VERSION 5.8 ;
BUSBITCHARS "[]" ;
DIVIDERCHAR "/" ;
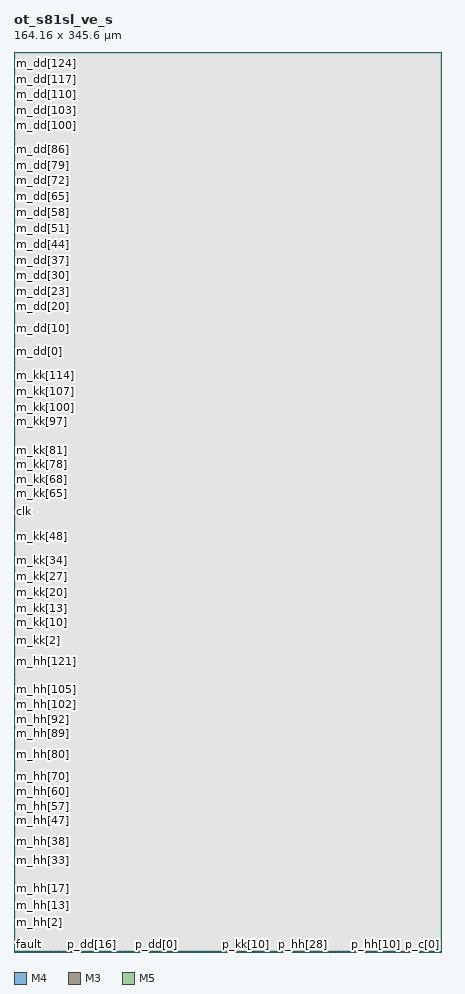
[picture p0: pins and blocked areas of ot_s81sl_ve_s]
MACRO ot_s81sl_ve_s
  CLASS BLOCK ;
  ORIGIN 0 0 ;
  FOREIGN ot_s81sl_ve_s 0 0 ;
  SIZE 164.160 BY 345.600 ;
  SYMMETRY X Y ;
  PIN clk
    DIRECTION INPUT ;
    USE SIGNAL ;
    PORT
      LAYER M4 ;
        RECT 0.0000 172.3200 0.0840 172.3440 ;
    END
  END clk
  PIN fault
    DIRECTION OUTPUT ;
    USE SIGNAL ;
    PORT
      LAYER M3 ;
        RECT 5.1120 0.0000 5.1300 0.0380 ;
    END
  END fault
  PIN m_dd[0]
    DIRECTION INPUT ;
    USE SIGNAL ;
    PORT
      LAYER M4 ;
        RECT 0.0000 230.4960 0.0840 230.5200 ;
    END
  END m_dd[0]
  PIN m_dd[100]
    DIRECTION INPUT ;
    USE SIGNAL ;
    PORT
      LAYER M4 ;
        RECT 0.0000 317.3760 0.0840 317.4000 ;
    END
  END m_dd[100]
  PIN m_dd[101]
    DIRECTION INPUT ;
    USE SIGNAL ;
    PORT
      LAYER M4 ;
        RECT 0.0000 318.2400 0.0840 318.2640 ;
    END
  END m_dd[101]
  PIN m_dd[102]
    DIRECTION INPUT ;
    USE SIGNAL ;
    PORT
      LAYER M4 ;
        RECT 0.0000 319.1040 0.0840 319.1280 ;
    END
  END m_dd[102]
  PIN m_dd[103]
    DIRECTION INPUT ;
    USE SIGNAL ;
    PORT
      LAYER M4 ;
        RECT 0.0000 319.9680 0.0840 319.9920 ;
    END
  END m_dd[103]
  PIN m_dd[104]
    DIRECTION INPUT ;
    USE SIGNAL ;
    PORT
      LAYER M4 ;
        RECT 0.0000 320.8320 0.0840 320.8560 ;
    END
  END m_dd[104]
  PIN m_dd[105]
    DIRECTION INPUT ;
    USE SIGNAL ;
    PORT
      LAYER M4 ;
        RECT 0.0000 321.6960 0.0840 321.7200 ;
    END
  END m_dd[105]
  PIN m_dd[106]
    DIRECTION INPUT ;
    USE SIGNAL ;
    PORT
      LAYER M4 ;
        RECT 0.0000 322.5600 0.0840 322.5840 ;
    END
  END m_dd[106]
  PIN m_dd[107]
    DIRECTION INPUT ;
    USE SIGNAL ;
    PORT
      LAYER M4 ;
        RECT 0.0000 323.4240 0.0840 323.4480 ;
    END
  END m_dd[107]
  PIN m_dd[108]
    DIRECTION INPUT ;
    USE SIGNAL ;
    PORT
      LAYER M4 ;
        RECT 0.0000 324.2880 0.0840 324.3120 ;
    END
  END m_dd[108]
  PIN m_dd[109]
    DIRECTION INPUT ;
    USE SIGNAL ;
    PORT
      LAYER M4 ;
        RECT 0.0000 325.2480 0.0840 325.2720 ;
    END
  END m_dd[109]
  PIN m_dd[10]
    DIRECTION INPUT ;
    USE SIGNAL ;
    PORT
      LAYER M4 ;
        RECT 0.0000 239.2320 0.0840 239.2560 ;
    END
  END m_dd[10]
  PIN m_dd[110]
    DIRECTION INPUT ;
    USE SIGNAL ;
    PORT
      LAYER M4 ;
        RECT 0.0000 326.1120 0.0840 326.1360 ;
    END
  END m_dd[110]
  PIN m_dd[111]
    DIRECTION INPUT ;
    USE SIGNAL ;
    PORT
      LAYER M4 ;
        RECT 0.0000 326.9760 0.0840 327.0000 ;
    END
  END m_dd[111]
  PIN m_dd[112]
    DIRECTION INPUT ;
    USE SIGNAL ;
    PORT
      LAYER M4 ;
        RECT 0.0000 327.8400 0.0840 327.8640 ;
    END
  END m_dd[112]
  PIN m_dd[113]
    DIRECTION INPUT ;
    USE SIGNAL ;
    PORT
      LAYER M4 ;
        RECT 0.0000 328.7040 0.0840 328.7280 ;
    END
  END m_dd[113]
  PIN m_dd[114]
    DIRECTION INPUT ;
    USE SIGNAL ;
    PORT
      LAYER M4 ;
        RECT 0.0000 329.5680 0.0840 329.5920 ;
    END
  END m_dd[114]
  PIN m_dd[115]
    DIRECTION INPUT ;
    USE SIGNAL ;
    PORT
      LAYER M4 ;
        RECT 0.0000 330.4320 0.0840 330.4560 ;
    END
  END m_dd[115]
  PIN m_dd[116]
    DIRECTION INPUT ;
    USE SIGNAL ;
    PORT
      LAYER M4 ;
        RECT 0.0000 331.2960 0.0840 331.3200 ;
    END
  END m_dd[116]
  PIN m_dd[117]
    DIRECTION INPUT ;
    USE SIGNAL ;
    PORT
      LAYER M4 ;
        RECT 0.0000 332.1600 0.0840 332.1840 ;
    END
  END m_dd[117]
  PIN m_dd[118]
    DIRECTION INPUT ;
    USE SIGNAL ;
    PORT
      LAYER M4 ;
        RECT 0.0000 333.0240 0.0840 333.0480 ;
    END
  END m_dd[118]
  PIN m_dd[119]
    DIRECTION INPUT ;
    USE SIGNAL ;
    PORT
      LAYER M4 ;
        RECT 0.0000 333.8880 0.0840 333.9120 ;
    END
  END m_dd[119]
  PIN m_dd[11]
    DIRECTION INPUT ;
    USE SIGNAL ;
    PORT
      LAYER M4 ;
        RECT 0.0000 240.0960 0.0840 240.1200 ;
    END
  END m_dd[11]
  PIN m_dd[120]
    DIRECTION INPUT ;
    USE SIGNAL ;
    PORT
      LAYER M4 ;
        RECT 0.0000 334.7520 0.0840 334.7760 ;
    END
  END m_dd[120]
  PIN m_dd[121]
    DIRECTION INPUT ;
    USE SIGNAL ;
    PORT
      LAYER M4 ;
        RECT 0.0000 335.6160 0.0840 335.6400 ;
    END
  END m_dd[121]
  PIN m_dd[122]
    DIRECTION INPUT ;
    USE SIGNAL ;
    PORT
      LAYER M4 ;
        RECT 0.0000 336.4800 0.0840 336.5040 ;
    END
  END m_dd[122]
  PIN m_dd[123]
    DIRECTION INPUT ;
    USE SIGNAL ;
    PORT
      LAYER M4 ;
        RECT 0.0000 337.3440 0.0840 337.3680 ;
    END
  END m_dd[123]
  PIN m_dd[124]
    DIRECTION INPUT ;
    USE SIGNAL ;
    PORT
      LAYER M4 ;
        RECT 0.0000 338.2080 0.0840 338.2320 ;
    END
  END m_dd[124]
  PIN m_dd[125]
    DIRECTION INPUT ;
    USE SIGNAL ;
    PORT
      LAYER M4 ;
        RECT 0.0000 339.0720 0.0840 339.0960 ;
    END
  END m_dd[125]
  PIN m_dd[126]
    DIRECTION INPUT ;
    USE SIGNAL ;
    PORT
      LAYER M4 ;
        RECT 0.0000 339.9360 0.0840 339.9600 ;
    END
  END m_dd[126]
  PIN m_dd[127]
    DIRECTION INPUT ;
    USE SIGNAL ;
    PORT
      LAYER M4 ;
        RECT 0.0000 340.8000 0.0840 340.8240 ;
    END
  END m_dd[127]
  PIN m_dd[12]
    DIRECTION INPUT ;
    USE SIGNAL ;
    PORT
      LAYER M4 ;
        RECT 0.0000 240.9600 0.0840 240.9840 ;
    END
  END m_dd[12]
  PIN m_dd[13]
    DIRECTION INPUT ;
    USE SIGNAL ;
    PORT
      LAYER M4 ;
        RECT 0.0000 241.8240 0.0840 241.8480 ;
    END
  END m_dd[13]
  PIN m_dd[14]
    DIRECTION INPUT ;
    USE SIGNAL ;
    PORT
      LAYER M4 ;
        RECT 0.0000 242.6880 0.0840 242.7120 ;
    END
  END m_dd[14]
  PIN m_dd[15]
    DIRECTION INPUT ;
    USE SIGNAL ;
    PORT
      LAYER M4 ;
        RECT 0.0000 243.5520 0.0840 243.5760 ;
    END
  END m_dd[15]
  PIN m_dd[16]
    DIRECTION INPUT ;
    USE SIGNAL ;
    PORT
      LAYER M4 ;
        RECT 0.0000 244.4160 0.0840 244.4400 ;
    END
  END m_dd[16]
  PIN m_dd[17]
    DIRECTION INPUT ;
    USE SIGNAL ;
    PORT
      LAYER M4 ;
        RECT 0.0000 245.2800 0.0840 245.3040 ;
    END
  END m_dd[17]
  PIN m_dd[18]
    DIRECTION INPUT ;
    USE SIGNAL ;
    PORT
      LAYER M4 ;
        RECT 0.0000 246.1440 0.0840 246.1680 ;
    END
  END m_dd[18]
  PIN m_dd[19]
    DIRECTION INPUT ;
    USE SIGNAL ;
    PORT
      LAYER M4 ;
        RECT 0.0000 247.0080 0.0840 247.0320 ;
    END
  END m_dd[19]
  PIN m_dd[1]
    DIRECTION INPUT ;
    USE SIGNAL ;
    PORT
      LAYER M4 ;
        RECT 0.0000 231.4560 0.0840 231.4800 ;
    END
  END m_dd[1]
  PIN m_dd[20]
    DIRECTION INPUT ;
    USE SIGNAL ;
    PORT
      LAYER M4 ;
        RECT 0.0000 247.8720 0.0840 247.8960 ;
    END
  END m_dd[20]
  PIN m_dd[21]
    DIRECTION INPUT ;
    USE SIGNAL ;
    PORT
      LAYER M4 ;
        RECT 0.0000 248.7360 0.0840 248.7600 ;
    END
  END m_dd[21]
  PIN m_dd[22]
    DIRECTION INPUT ;
    USE SIGNAL ;
    PORT
      LAYER M4 ;
        RECT 0.0000 249.6000 0.0840 249.6240 ;
    END
  END m_dd[22]
  PIN m_dd[23]
    DIRECTION INPUT ;
    USE SIGNAL ;
    PORT
      LAYER M4 ;
        RECT 0.0000 250.5600 0.0840 250.5840 ;
    END
  END m_dd[23]
  PIN m_dd[24]
    DIRECTION INPUT ;
    USE SIGNAL ;
    PORT
      LAYER M4 ;
        RECT 0.0000 251.4240 0.0840 251.4480 ;
    END
  END m_dd[24]
  PIN m_dd[25]
    DIRECTION INPUT ;
    USE SIGNAL ;
    PORT
      LAYER M4 ;
        RECT 0.0000 252.2880 0.0840 252.3120 ;
    END
  END m_dd[25]
  PIN m_dd[26]
    DIRECTION INPUT ;
    USE SIGNAL ;
    PORT
      LAYER M4 ;
        RECT 0.0000 253.1520 0.0840 253.1760 ;
    END
  END m_dd[26]
  PIN m_dd[27]
    DIRECTION INPUT ;
    USE SIGNAL ;
    PORT
      LAYER M4 ;
        RECT 0.0000 254.0160 0.0840 254.0400 ;
    END
  END m_dd[27]
  PIN m_dd[28]
    DIRECTION INPUT ;
    USE SIGNAL ;
    PORT
      LAYER M4 ;
        RECT 0.0000 254.8800 0.0840 254.9040 ;
    END
  END m_dd[28]
  PIN m_dd[29]
    DIRECTION INPUT ;
    USE SIGNAL ;
    PORT
      LAYER M4 ;
        RECT 0.0000 255.7440 0.0840 255.7680 ;
    END
  END m_dd[29]
  PIN m_dd[2]
    DIRECTION INPUT ;
    USE SIGNAL ;
    PORT
      LAYER M4 ;
        RECT 0.0000 232.3200 0.0840 232.3440 ;
    END
  END m_dd[2]
  PIN m_dd[30]
    DIRECTION INPUT ;
    USE SIGNAL ;
    PORT
      LAYER M4 ;
        RECT 0.0000 256.6080 0.0840 256.6320 ;
    END
  END m_dd[30]
  PIN m_dd[31]
    DIRECTION INPUT ;
    USE SIGNAL ;
    PORT
      LAYER M4 ;
        RECT 0.0000 257.4720 0.0840 257.4960 ;
    END
  END m_dd[31]
  PIN m_dd[32]
    DIRECTION INPUT ;
    USE SIGNAL ;
    PORT
      LAYER M4 ;
        RECT 0.0000 258.3360 0.0840 258.3600 ;
    END
  END m_dd[32]
  PIN m_dd[33]
    DIRECTION INPUT ;
    USE SIGNAL ;
    PORT
      LAYER M4 ;
        RECT 0.0000 259.2000 0.0840 259.2240 ;
    END
  END m_dd[33]
  PIN m_dd[34]
    DIRECTION INPUT ;
    USE SIGNAL ;
    PORT
      LAYER M4 ;
        RECT 0.0000 260.0640 0.0840 260.0880 ;
    END
  END m_dd[34]
  PIN m_dd[35]
    DIRECTION INPUT ;
    USE SIGNAL ;
    PORT
      LAYER M4 ;
        RECT 0.0000 260.9280 0.0840 260.9520 ;
    END
  END m_dd[35]
  PIN m_dd[36]
    DIRECTION INPUT ;
    USE SIGNAL ;
    PORT
      LAYER M4 ;
        RECT 0.0000 261.7920 0.0840 261.8160 ;
    END
  END m_dd[36]
  PIN m_dd[37]
    DIRECTION INPUT ;
    USE SIGNAL ;
    PORT
      LAYER M4 ;
        RECT 0.0000 262.6560 0.0840 262.6800 ;
    END
  END m_dd[37]
  PIN m_dd[38]
    DIRECTION INPUT ;
    USE SIGNAL ;
    PORT
      LAYER M4 ;
        RECT 0.0000 263.5200 0.0840 263.5440 ;
    END
  END m_dd[38]
  PIN m_dd[39]
    DIRECTION INPUT ;
    USE SIGNAL ;
    PORT
      LAYER M4 ;
        RECT 0.0000 264.3840 0.0840 264.4080 ;
    END
  END m_dd[39]
  PIN m_dd[3]
    DIRECTION INPUT ;
    USE SIGNAL ;
    PORT
      LAYER M4 ;
        RECT 0.0000 233.1840 0.0840 233.2080 ;
    END
  END m_dd[3]
  PIN m_dd[40]
    DIRECTION INPUT ;
    USE SIGNAL ;
    PORT
      LAYER M4 ;
        RECT 0.0000 265.2480 0.0840 265.2720 ;
    END
  END m_dd[40]
  PIN m_dd[41]
    DIRECTION INPUT ;
    USE SIGNAL ;
    PORT
      LAYER M4 ;
        RECT 0.0000 266.1120 0.0840 266.1360 ;
    END
  END m_dd[41]
  PIN m_dd[42]
    DIRECTION INPUT ;
    USE SIGNAL ;
    PORT
      LAYER M4 ;
        RECT 0.0000 266.9760 0.0840 267.0000 ;
    END
  END m_dd[42]
  PIN m_dd[43]
    DIRECTION INPUT ;
    USE SIGNAL ;
    PORT
      LAYER M4 ;
        RECT 0.0000 267.8400 0.0840 267.8640 ;
    END
  END m_dd[43]
  PIN m_dd[44]
    DIRECTION INPUT ;
    USE SIGNAL ;
    PORT
      LAYER M4 ;
        RECT 0.0000 268.8000 0.0840 268.8240 ;
    END
  END m_dd[44]
  PIN m_dd[45]
    DIRECTION INPUT ;
    USE SIGNAL ;
    PORT
      LAYER M4 ;
        RECT 0.0000 269.6640 0.0840 269.6880 ;
    END
  END m_dd[45]
  PIN m_dd[46]
    DIRECTION INPUT ;
    USE SIGNAL ;
    PORT
      LAYER M4 ;
        RECT 0.0000 270.5280 0.0840 270.5520 ;
    END
  END m_dd[46]
  PIN m_dd[47]
    DIRECTION INPUT ;
    USE SIGNAL ;
    PORT
      LAYER M4 ;
        RECT 0.0000 271.3920 0.0840 271.4160 ;
    END
  END m_dd[47]
  PIN m_dd[48]
    DIRECTION INPUT ;
    USE SIGNAL ;
    PORT
      LAYER M4 ;
        RECT 0.0000 272.2560 0.0840 272.2800 ;
    END
  END m_dd[48]
  PIN m_dd[49]
    DIRECTION INPUT ;
    USE SIGNAL ;
    PORT
      LAYER M4 ;
        RECT 0.0000 273.1200 0.0840 273.1440 ;
    END
  END m_dd[49]
  PIN m_dd[4]
    DIRECTION INPUT ;
    USE SIGNAL ;
    PORT
      LAYER M4 ;
        RECT 0.0000 234.0480 0.0840 234.0720 ;
    END
  END m_dd[4]
  PIN m_dd[50]
    DIRECTION INPUT ;
    USE SIGNAL ;
    PORT
      LAYER M4 ;
        RECT 0.0000 273.9840 0.0840 274.0080 ;
    END
  END m_dd[50]
  PIN m_dd[51]
    DIRECTION INPUT ;
    USE SIGNAL ;
    PORT
      LAYER M4 ;
        RECT 0.0000 274.8480 0.0840 274.8720 ;
    END
  END m_dd[51]
  PIN m_dd[52]
    DIRECTION INPUT ;
    USE SIGNAL ;
    PORT
      LAYER M4 ;
        RECT 0.0000 275.7120 0.0840 275.7360 ;
    END
  END m_dd[52]
  PIN m_dd[53]
    DIRECTION INPUT ;
    USE SIGNAL ;
    PORT
      LAYER M4 ;
        RECT 0.0000 276.5760 0.0840 276.6000 ;
    END
  END m_dd[53]
  PIN m_dd[54]
    DIRECTION INPUT ;
    USE SIGNAL ;
    PORT
      LAYER M4 ;
        RECT 0.0000 277.4400 0.0840 277.4640 ;
    END
  END m_dd[54]
  PIN m_dd[55]
    DIRECTION INPUT ;
    USE SIGNAL ;
    PORT
      LAYER M4 ;
        RECT 0.0000 278.3040 0.0840 278.3280 ;
    END
  END m_dd[55]
  PIN m_dd[56]
    DIRECTION INPUT ;
    USE SIGNAL ;
    PORT
      LAYER M4 ;
        RECT 0.0000 279.1680 0.0840 279.1920 ;
    END
  END m_dd[56]
  PIN m_dd[57]
    DIRECTION INPUT ;
    USE SIGNAL ;
    PORT
      LAYER M4 ;
        RECT 0.0000 280.0320 0.0840 280.0560 ;
    END
  END m_dd[57]
  PIN m_dd[58]
    DIRECTION INPUT ;
    USE SIGNAL ;
    PORT
      LAYER M4 ;
        RECT 0.0000 280.8960 0.0840 280.9200 ;
    END
  END m_dd[58]
  PIN m_dd[59]
    DIRECTION INPUT ;
    USE SIGNAL ;
    PORT
      LAYER M4 ;
        RECT 0.0000 281.7600 0.0840 281.7840 ;
    END
  END m_dd[59]
  PIN m_dd[5]
    DIRECTION INPUT ;
    USE SIGNAL ;
    PORT
      LAYER M4 ;
        RECT 0.0000 234.9120 0.0840 234.9360 ;
    END
  END m_dd[5]
  PIN m_dd[60]
    DIRECTION INPUT ;
    USE SIGNAL ;
    PORT
      LAYER M4 ;
        RECT 0.0000 282.6240 0.0840 282.6480 ;
    END
  END m_dd[60]
  PIN m_dd[61]
    DIRECTION INPUT ;
    USE SIGNAL ;
    PORT
      LAYER M4 ;
        RECT 0.0000 283.4880 0.0840 283.5120 ;
    END
  END m_dd[61]
  PIN m_dd[62]
    DIRECTION INPUT ;
    USE SIGNAL ;
    PORT
      LAYER M4 ;
        RECT 0.0000 284.3520 0.0840 284.3760 ;
    END
  END m_dd[62]
  PIN m_dd[63]
    DIRECTION INPUT ;
    USE SIGNAL ;
    PORT
      LAYER M4 ;
        RECT 0.0000 285.2160 0.0840 285.2400 ;
    END
  END m_dd[63]
  PIN m_dd[64]
    DIRECTION INPUT ;
    USE SIGNAL ;
    PORT
      LAYER M4 ;
        RECT 0.0000 286.0800 0.0840 286.1040 ;
    END
  END m_dd[64]
  PIN m_dd[65]
    DIRECTION INPUT ;
    USE SIGNAL ;
    PORT
      LAYER M4 ;
        RECT 0.0000 286.9440 0.0840 286.9680 ;
    END
  END m_dd[65]
  PIN m_dd[66]
    DIRECTION INPUT ;
    USE SIGNAL ;
    PORT
      LAYER M4 ;
        RECT 0.0000 287.9040 0.0840 287.9280 ;
    END
  END m_dd[66]
  PIN m_dd[67]
    DIRECTION INPUT ;
    USE SIGNAL ;
    PORT
      LAYER M4 ;
        RECT 0.0000 288.7680 0.0840 288.7920 ;
    END
  END m_dd[67]
  PIN m_dd[68]
    DIRECTION INPUT ;
    USE SIGNAL ;
    PORT
      LAYER M4 ;
        RECT 0.0000 289.6320 0.0840 289.6560 ;
    END
  END m_dd[68]
  PIN m_dd[69]
    DIRECTION INPUT ;
    USE SIGNAL ;
    PORT
      LAYER M4 ;
        RECT 0.0000 290.4960 0.0840 290.5200 ;
    END
  END m_dd[69]
  PIN m_dd[6]
    DIRECTION INPUT ;
    USE SIGNAL ;
    PORT
      LAYER M4 ;
        RECT 0.0000 235.7760 0.0840 235.8000 ;
    END
  END m_dd[6]
  PIN m_dd[70]
    DIRECTION INPUT ;
    USE SIGNAL ;
    PORT
      LAYER M4 ;
        RECT 0.0000 291.3600 0.0840 291.3840 ;
    END
  END m_dd[70]
  PIN m_dd[71]
    DIRECTION INPUT ;
    USE SIGNAL ;
    PORT
      LAYER M4 ;
        RECT 0.0000 292.2240 0.0840 292.2480 ;
    END
  END m_dd[71]
  PIN m_dd[72]
    DIRECTION INPUT ;
    USE SIGNAL ;
    PORT
      LAYER M4 ;
        RECT 0.0000 293.0880 0.0840 293.1120 ;
    END
  END m_dd[72]
  PIN m_dd[73]
    DIRECTION INPUT ;
    USE SIGNAL ;
    PORT
      LAYER M4 ;
        RECT 0.0000 293.9520 0.0840 293.9760 ;
    END
  END m_dd[73]
  PIN m_dd[74]
    DIRECTION INPUT ;
    USE SIGNAL ;
    PORT
      LAYER M4 ;
        RECT 0.0000 294.8160 0.0840 294.8400 ;
    END
  END m_dd[74]
  PIN m_dd[75]
    DIRECTION INPUT ;
    USE SIGNAL ;
    PORT
      LAYER M4 ;
        RECT 0.0000 295.6800 0.0840 295.7040 ;
    END
  END m_dd[75]
  PIN m_dd[76]
    DIRECTION INPUT ;
    USE SIGNAL ;
    PORT
      LAYER M4 ;
        RECT 0.0000 296.5440 0.0840 296.5680 ;
    END
  END m_dd[76]
  PIN m_dd[77]
    DIRECTION INPUT ;
    USE SIGNAL ;
    PORT
      LAYER M4 ;
        RECT 0.0000 297.4080 0.0840 297.4320 ;
    END
  END m_dd[77]
  PIN m_dd[78]
    DIRECTION INPUT ;
    USE SIGNAL ;
    PORT
      LAYER M4 ;
        RECT 0.0000 298.2720 0.0840 298.2960 ;
    END
  END m_dd[78]
  PIN m_dd[79]
    DIRECTION INPUT ;
    USE SIGNAL ;
    PORT
      LAYER M4 ;
        RECT 0.0000 299.1360 0.0840 299.1600 ;
    END
  END m_dd[79]
  PIN m_dd[7]
    DIRECTION INPUT ;
    USE SIGNAL ;
    PORT
      LAYER M4 ;
        RECT 0.0000 236.6400 0.0840 236.6640 ;
    END
  END m_dd[7]
  PIN m_dd[80]
    DIRECTION INPUT ;
    USE SIGNAL ;
    PORT
      LAYER M4 ;
        RECT 0.0000 300.0000 0.0840 300.0240 ;
    END
  END m_dd[80]
  PIN m_dd[81]
    DIRECTION INPUT ;
    USE SIGNAL ;
    PORT
      LAYER M4 ;
        RECT 0.0000 300.8640 0.0840 300.8880 ;
    END
  END m_dd[81]
  PIN m_dd[82]
    DIRECTION INPUT ;
    USE SIGNAL ;
    PORT
      LAYER M4 ;
        RECT 0.0000 301.7280 0.0840 301.7520 ;
    END
  END m_dd[82]
  PIN m_dd[83]
    DIRECTION INPUT ;
    USE SIGNAL ;
    PORT
      LAYER M4 ;
        RECT 0.0000 302.5920 0.0840 302.6160 ;
    END
  END m_dd[83]
  PIN m_dd[84]
    DIRECTION INPUT ;
    USE SIGNAL ;
    PORT
      LAYER M4 ;
        RECT 0.0000 303.4560 0.0840 303.4800 ;
    END
  END m_dd[84]
  PIN m_dd[85]
    DIRECTION INPUT ;
    USE SIGNAL ;
    PORT
      LAYER M4 ;
        RECT 0.0000 304.3200 0.0840 304.3440 ;
    END
  END m_dd[85]
  PIN m_dd[86]
    DIRECTION INPUT ;
    USE SIGNAL ;
    PORT
      LAYER M4 ;
        RECT 0.0000 305.1840 0.0840 305.2080 ;
    END
  END m_dd[86]
  PIN m_dd[87]
    DIRECTION INPUT ;
    USE SIGNAL ;
    PORT
      LAYER M4 ;
        RECT 0.0000 306.0480 0.0840 306.0720 ;
    END
  END m_dd[87]
  PIN m_dd[88]
    DIRECTION INPUT ;
    USE SIGNAL ;
    PORT
      LAYER M4 ;
        RECT 0.0000 307.0080 0.0840 307.0320 ;
    END
  END m_dd[88]
  PIN m_dd[89]
    DIRECTION INPUT ;
    USE SIGNAL ;
    PORT
      LAYER M4 ;
        RECT 0.0000 307.8720 0.0840 307.8960 ;
    END
  END m_dd[89]
  PIN m_dd[8]
    DIRECTION INPUT ;
    USE SIGNAL ;
    PORT
      LAYER M4 ;
        RECT 0.0000 237.5040 0.0840 237.5280 ;
    END
  END m_dd[8]
  PIN m_dd[90]
    DIRECTION INPUT ;
    USE SIGNAL ;
    PORT
      LAYER M4 ;
        RECT 0.0000 308.7360 0.0840 308.7600 ;
    END
  END m_dd[90]
  PIN m_dd[91]
    DIRECTION INPUT ;
    USE SIGNAL ;
    PORT
      LAYER M4 ;
        RECT 0.0000 309.6000 0.0840 309.6240 ;
    END
  END m_dd[91]
  PIN m_dd[92]
    DIRECTION INPUT ;
    USE SIGNAL ;
    PORT
      LAYER M4 ;
        RECT 0.0000 310.4640 0.0840 310.4880 ;
    END
  END m_dd[92]
  PIN m_dd[93]
    DIRECTION INPUT ;
    USE SIGNAL ;
    PORT
      LAYER M4 ;
        RECT 0.0000 311.3280 0.0840 311.3520 ;
    END
  END m_dd[93]
  PIN m_dd[94]
    DIRECTION INPUT ;
    USE SIGNAL ;
    PORT
      LAYER M4 ;
        RECT 0.0000 312.1920 0.0840 312.2160 ;
    END
  END m_dd[94]
  PIN m_dd[95]
    DIRECTION INPUT ;
    USE SIGNAL ;
    PORT
      LAYER M4 ;
        RECT 0.0000 313.0560 0.0840 313.0800 ;
    END
  END m_dd[95]
  PIN m_dd[96]
    DIRECTION INPUT ;
    USE SIGNAL ;
    PORT
      LAYER M4 ;
        RECT 0.0000 313.9200 0.0840 313.9440 ;
    END
  END m_dd[96]
  PIN m_dd[97]
    DIRECTION INPUT ;
    USE SIGNAL ;
    PORT
      LAYER M4 ;
        RECT 0.0000 314.7840 0.0840 314.8080 ;
    END
  END m_dd[97]
  PIN m_dd[98]
    DIRECTION INPUT ;
    USE SIGNAL ;
    PORT
      LAYER M4 ;
        RECT 0.0000 315.6480 0.0840 315.6720 ;
    END
  END m_dd[98]
  PIN m_dd[99]
    DIRECTION INPUT ;
    USE SIGNAL ;
    PORT
      LAYER M4 ;
        RECT 0.0000 316.5120 0.0840 316.5360 ;
    END
  END m_dd[99]
  PIN m_dd[9]
    DIRECTION INPUT ;
    USE SIGNAL ;
    PORT
      LAYER M4 ;
        RECT 0.0000 238.3680 0.0840 238.3920 ;
    END
  END m_dd[9]
  PIN m_hh[0]
    DIRECTION INPUT ;
    USE SIGNAL ;
    PORT
      LAYER M4 ;
        RECT 0.0000 6.4320 0.0840 6.4560 ;
    END
  END m_hh[0]
  PIN m_hh[100]
    DIRECTION INPUT ;
    USE SIGNAL ;
    PORT
      LAYER M4 ;
        RECT 0.0000 93.3120 0.0840 93.3360 ;
    END
  END m_hh[100]
  PIN m_hh[101]
    DIRECTION INPUT ;
    USE SIGNAL ;
    PORT
      LAYER M4 ;
        RECT 0.0000 94.1760 0.0840 94.2000 ;
    END
  END m_hh[101]
  PIN m_hh[102]
    DIRECTION INPUT ;
    USE SIGNAL ;
    PORT
      LAYER M4 ;
        RECT 0.0000 95.0400 0.0840 95.0640 ;
    END
  END m_hh[102]
  PIN m_hh[103]
    DIRECTION INPUT ;
    USE SIGNAL ;
    PORT
      LAYER M4 ;
        RECT 0.0000 95.9040 0.0840 95.9280 ;
    END
  END m_hh[103]
  PIN m_hh[104]
    DIRECTION INPUT ;
    USE SIGNAL ;
    PORT
      LAYER M4 ;
        RECT 0.0000 96.7680 0.0840 96.7920 ;
    END
  END m_hh[104]
  PIN m_hh[105]
    DIRECTION INPUT ;
    USE SIGNAL ;
    PORT
      LAYER M4 ;
        RECT 0.0000 97.6320 0.0840 97.6560 ;
    END
  END m_hh[105]
  PIN m_hh[106]
    DIRECTION INPUT ;
    USE SIGNAL ;
    PORT
      LAYER M4 ;
        RECT 0.0000 98.4960 0.0840 98.5200 ;
    END
  END m_hh[106]
  PIN m_hh[107]
    DIRECTION INPUT ;
    USE SIGNAL ;
    PORT
      LAYER M4 ;
        RECT 0.0000 99.3600 0.0840 99.3840 ;
    END
  END m_hh[107]
  PIN m_hh[108]
    DIRECTION INPUT ;
    USE SIGNAL ;
    PORT
      LAYER M4 ;
        RECT 0.0000 100.3200 0.0840 100.3440 ;
    END
  END m_hh[108]
  PIN m_hh[109]
    DIRECTION INPUT ;
    USE SIGNAL ;
    PORT
      LAYER M4 ;
        RECT 0.0000 101.1840 0.0840 101.2080 ;
    END
  END m_hh[109]
  PIN m_hh[10]
    DIRECTION INPUT ;
    USE SIGNAL ;
    PORT
      LAYER M4 ;
        RECT 0.0000 15.1680 0.0840 15.1920 ;
    END
  END m_hh[10]
  PIN m_hh[110]
    DIRECTION INPUT ;
    USE SIGNAL ;
    PORT
      LAYER M4 ;
        RECT 0.0000 102.0480 0.0840 102.0720 ;
    END
  END m_hh[110]
  PIN m_hh[111]
    DIRECTION INPUT ;
    USE SIGNAL ;
    PORT
      LAYER M4 ;
        RECT 0.0000 102.9120 0.0840 102.9360 ;
    END
  END m_hh[111]
  PIN m_hh[112]
    DIRECTION INPUT ;
    USE SIGNAL ;
    PORT
      LAYER M4 ;
        RECT 0.0000 103.7760 0.0840 103.8000 ;
    END
  END m_hh[112]
  PIN m_hh[113]
    DIRECTION INPUT ;
    USE SIGNAL ;
    PORT
      LAYER M4 ;
        RECT 0.0000 104.6400 0.0840 104.6640 ;
    END
  END m_hh[113]
  PIN m_hh[114]
    DIRECTION INPUT ;
    USE SIGNAL ;
    PORT
      LAYER M4 ;
        RECT 0.0000 105.5040 0.0840 105.5280 ;
    END
  END m_hh[114]
  PIN m_hh[115]
    DIRECTION INPUT ;
    USE SIGNAL ;
    PORT
      LAYER M4 ;
        RECT 0.0000 106.3680 0.0840 106.3920 ;
    END
  END m_hh[115]
  PIN m_hh[116]
    DIRECTION INPUT ;
    USE SIGNAL ;
    PORT
      LAYER M4 ;
        RECT 0.0000 107.2320 0.0840 107.2560 ;
    END
  END m_hh[116]
  PIN m_hh[117]
    DIRECTION INPUT ;
    USE SIGNAL ;
    PORT
      LAYER M4 ;
        RECT 0.0000 108.0960 0.0840 108.1200 ;
    END
  END m_hh[117]
  PIN m_hh[118]
    DIRECTION INPUT ;
    USE SIGNAL ;
    PORT
      LAYER M4 ;
        RECT 0.0000 108.9600 0.0840 108.9840 ;
    END
  END m_hh[118]
  PIN m_hh[119]
    DIRECTION INPUT ;
    USE SIGNAL ;
    PORT
      LAYER M4 ;
        RECT 0.0000 109.8240 0.0840 109.8480 ;
    END
  END m_hh[119]
  PIN m_hh[11]
    DIRECTION INPUT ;
    USE SIGNAL ;
    PORT
      LAYER M4 ;
        RECT 0.0000 16.0320 0.0840 16.0560 ;
    END
  END m_hh[11]
  PIN m_hh[120]
    DIRECTION INPUT ;
    USE SIGNAL ;
    PORT
      LAYER M4 ;
        RECT 0.0000 110.6880 0.0840 110.7120 ;
    END
  END m_hh[120]
  PIN m_hh[121]
    DIRECTION INPUT ;
    USE SIGNAL ;
    PORT
      LAYER M4 ;
        RECT 0.0000 111.5520 0.0840 111.5760 ;
    END
  END m_hh[121]
  PIN m_hh[122]
    DIRECTION INPUT ;
    USE SIGNAL ;
    PORT
      LAYER M4 ;
        RECT 0.0000 112.4160 0.0840 112.4400 ;
    END
  END m_hh[122]
  PIN m_hh[123]
    DIRECTION INPUT ;
    USE SIGNAL ;
    PORT
      LAYER M4 ;
        RECT 0.0000 113.2800 0.0840 113.3040 ;
    END
  END m_hh[123]
  PIN m_hh[124]
    DIRECTION INPUT ;
    USE SIGNAL ;
    PORT
      LAYER M4 ;
        RECT 0.0000 114.1440 0.0840 114.1680 ;
    END
  END m_hh[124]
  PIN m_hh[125]
    DIRECTION INPUT ;
    USE SIGNAL ;
    PORT
      LAYER M4 ;
        RECT 0.0000 115.0080 0.0840 115.0320 ;
    END
  END m_hh[125]
  PIN m_hh[126]
    DIRECTION INPUT ;
    USE SIGNAL ;
    PORT
      LAYER M4 ;
        RECT 0.0000 115.8720 0.0840 115.8960 ;
    END
  END m_hh[126]
  PIN m_hh[127]
    DIRECTION INPUT ;
    USE SIGNAL ;
    PORT
      LAYER M4 ;
        RECT 0.0000 116.7360 0.0840 116.7600 ;
    END
  END m_hh[127]
  PIN m_hh[12]
    DIRECTION INPUT ;
    USE SIGNAL ;
    PORT
      LAYER M4 ;
        RECT 0.0000 16.8960 0.0840 16.9200 ;
    END
  END m_hh[12]
  PIN m_hh[13]
    DIRECTION INPUT ;
    USE SIGNAL ;
    PORT
      LAYER M4 ;
        RECT 0.0000 17.7600 0.0840 17.7840 ;
    END
  END m_hh[13]
  PIN m_hh[14]
    DIRECTION INPUT ;
    USE SIGNAL ;
    PORT
      LAYER M4 ;
        RECT 0.0000 18.6240 0.0840 18.6480 ;
    END
  END m_hh[14]
  PIN m_hh[15]
    DIRECTION INPUT ;
    USE SIGNAL ;
    PORT
      LAYER M4 ;
        RECT 0.0000 19.4880 0.0840 19.5120 ;
    END
  END m_hh[15]
  PIN m_hh[16]
    DIRECTION INPUT ;
    USE SIGNAL ;
    PORT
      LAYER M4 ;
        RECT 0.0000 20.3520 0.0840 20.3760 ;
    END
  END m_hh[16]
  PIN m_hh[17]
    DIRECTION INPUT ;
    USE SIGNAL ;
    PORT
      LAYER M4 ;
        RECT 0.0000 21.2160 0.0840 21.2400 ;
    END
  END m_hh[17]
  PIN m_hh[18]
    DIRECTION INPUT ;
    USE SIGNAL ;
    PORT
      LAYER M4 ;
        RECT 0.0000 22.0800 0.0840 22.1040 ;
    END
  END m_hh[18]
  PIN m_hh[19]
    DIRECTION INPUT ;
    USE SIGNAL ;
    PORT
      LAYER M4 ;
        RECT 0.0000 22.9440 0.0840 22.9680 ;
    END
  END m_hh[19]
  PIN m_hh[1]
    DIRECTION INPUT ;
    USE SIGNAL ;
    PORT
      LAYER M4 ;
        RECT 0.0000 7.3920 0.0840 7.4160 ;
    END
  END m_hh[1]
  PIN m_hh[20]
    DIRECTION INPUT ;
    USE SIGNAL ;
    PORT
      LAYER M4 ;
        RECT 0.0000 23.8080 0.0840 23.8320 ;
    END
  END m_hh[20]
  PIN m_hh[21]
    DIRECTION INPUT ;
    USE SIGNAL ;
    PORT
      LAYER M4 ;
        RECT 0.0000 24.6720 0.0840 24.6960 ;
    END
  END m_hh[21]
  PIN m_hh[22]
    DIRECTION INPUT ;
    USE SIGNAL ;
    PORT
      LAYER M4 ;
        RECT 0.0000 25.6320 0.0840 25.6560 ;
    END
  END m_hh[22]
  PIN m_hh[23]
    DIRECTION INPUT ;
    USE SIGNAL ;
    PORT
      LAYER M4 ;
        RECT 0.0000 26.4960 0.0840 26.5200 ;
    END
  END m_hh[23]
  PIN m_hh[24]
    DIRECTION INPUT ;
    USE SIGNAL ;
    PORT
      LAYER M4 ;
        RECT 0.0000 27.3600 0.0840 27.3840 ;
    END
  END m_hh[24]
  PIN m_hh[25]
    DIRECTION INPUT ;
    USE SIGNAL ;
    PORT
      LAYER M4 ;
        RECT 0.0000 28.2240 0.0840 28.2480 ;
    END
  END m_hh[25]
  PIN m_hh[26]
    DIRECTION INPUT ;
    USE SIGNAL ;
    PORT
      LAYER M4 ;
        RECT 0.0000 29.0880 0.0840 29.1120 ;
    END
  END m_hh[26]
  PIN m_hh[27]
    DIRECTION INPUT ;
    USE SIGNAL ;
    PORT
      LAYER M4 ;
        RECT 0.0000 29.9520 0.0840 29.9760 ;
    END
  END m_hh[27]
  PIN m_hh[28]
    DIRECTION INPUT ;
    USE SIGNAL ;
    PORT
      LAYER M4 ;
        RECT 0.0000 30.8160 0.0840 30.8400 ;
    END
  END m_hh[28]
  PIN m_hh[29]
    DIRECTION INPUT ;
    USE SIGNAL ;
    PORT
      LAYER M4 ;
        RECT 0.0000 31.6800 0.0840 31.7040 ;
    END
  END m_hh[29]
  PIN m_hh[2]
    DIRECTION INPUT ;
    USE SIGNAL ;
    PORT
      LAYER M4 ;
        RECT 0.0000 8.2560 0.0840 8.2800 ;
    END
  END m_hh[2]
  PIN m_hh[30]
    DIRECTION INPUT ;
    USE SIGNAL ;
    PORT
      LAYER M4 ;
        RECT 0.0000 32.5440 0.0840 32.5680 ;
    END
  END m_hh[30]
  PIN m_hh[31]
    DIRECTION INPUT ;
    USE SIGNAL ;
    PORT
      LAYER M4 ;
        RECT 0.0000 33.4080 0.0840 33.4320 ;
    END
  END m_hh[31]
  PIN m_hh[32]
    DIRECTION INPUT ;
    USE SIGNAL ;
    PORT
      LAYER M4 ;
        RECT 0.0000 34.2720 0.0840 34.2960 ;
    END
  END m_hh[32]
  PIN m_hh[33]
    DIRECTION INPUT ;
    USE SIGNAL ;
    PORT
      LAYER M4 ;
        RECT 0.0000 35.1360 0.0840 35.1600 ;
    END
  END m_hh[33]
  PIN m_hh[34]
    DIRECTION INPUT ;
    USE SIGNAL ;
    PORT
      LAYER M4 ;
        RECT 0.0000 36.0000 0.0840 36.0240 ;
    END
  END m_hh[34]
  PIN m_hh[35]
    DIRECTION INPUT ;
    USE SIGNAL ;
    PORT
      LAYER M4 ;
        RECT 0.0000 36.8640 0.0840 36.8880 ;
    END
  END m_hh[35]
  PIN m_hh[36]
    DIRECTION INPUT ;
    USE SIGNAL ;
    PORT
      LAYER M4 ;
        RECT 0.0000 37.7280 0.0840 37.7520 ;
    END
  END m_hh[36]
  PIN m_hh[37]
    DIRECTION INPUT ;
    USE SIGNAL ;
    PORT
      LAYER M4 ;
        RECT 0.0000 38.5920 0.0840 38.6160 ;
    END
  END m_hh[37]
  PIN m_hh[38]
    DIRECTION INPUT ;
    USE SIGNAL ;
    PORT
      LAYER M4 ;
        RECT 0.0000 39.4560 0.0840 39.4800 ;
    END
  END m_hh[38]
  PIN m_hh[39]
    DIRECTION INPUT ;
    USE SIGNAL ;
    PORT
      LAYER M4 ;
        RECT 0.0000 40.3200 0.0840 40.3440 ;
    END
  END m_hh[39]
  PIN m_hh[3]
    DIRECTION INPUT ;
    USE SIGNAL ;
    PORT
      LAYER M4 ;
        RECT 0.0000 9.1200 0.0840 9.1440 ;
    END
  END m_hh[3]
  PIN m_hh[40]
    DIRECTION INPUT ;
    USE SIGNAL ;
    PORT
      LAYER M4 ;
        RECT 0.0000 41.1840 0.0840 41.2080 ;
    END
  END m_hh[40]
  PIN m_hh[41]
    DIRECTION INPUT ;
    USE SIGNAL ;
    PORT
      LAYER M4 ;
        RECT 0.0000 42.0480 0.0840 42.0720 ;
    END
  END m_hh[41]
  PIN m_hh[42]
    DIRECTION INPUT ;
    USE SIGNAL ;
    PORT
      LAYER M4 ;
        RECT 0.0000 42.9120 0.0840 42.9360 ;
    END
  END m_hh[42]
  PIN m_hh[43]
    DIRECTION INPUT ;
    USE SIGNAL ;
    PORT
      LAYER M4 ;
        RECT 0.0000 43.7760 0.0840 43.8000 ;
    END
  END m_hh[43]
  PIN m_hh[44]
    DIRECTION INPUT ;
    USE SIGNAL ;
    PORT
      LAYER M4 ;
        RECT 0.0000 44.7360 0.0840 44.7600 ;
    END
  END m_hh[44]
  PIN m_hh[45]
    DIRECTION INPUT ;
    USE SIGNAL ;
    PORT
      LAYER M4 ;
        RECT 0.0000 45.6000 0.0840 45.6240 ;
    END
  END m_hh[45]
  PIN m_hh[46]
    DIRECTION INPUT ;
    USE SIGNAL ;
    PORT
      LAYER M4 ;
        RECT 0.0000 46.4640 0.0840 46.4880 ;
    END
  END m_hh[46]
  PIN m_hh[47]
    DIRECTION INPUT ;
    USE SIGNAL ;
    PORT
      LAYER M4 ;
        RECT 0.0000 47.3280 0.0840 47.3520 ;
    END
  END m_hh[47]
  PIN m_hh[48]
    DIRECTION INPUT ;
    USE SIGNAL ;
    PORT
      LAYER M4 ;
        RECT 0.0000 48.1920 0.0840 48.2160 ;
    END
  END m_hh[48]
  PIN m_hh[49]
    DIRECTION INPUT ;
    USE SIGNAL ;
    PORT
      LAYER M4 ;
        RECT 0.0000 49.0560 0.0840 49.0800 ;
    END
  END m_hh[49]
  PIN m_hh[4]
    DIRECTION INPUT ;
    USE SIGNAL ;
    PORT
      LAYER M4 ;
        RECT 0.0000 9.9840 0.0840 10.0080 ;
    END
  END m_hh[4]
  PIN m_hh[50]
    DIRECTION INPUT ;
    USE SIGNAL ;
    PORT
      LAYER M4 ;
        RECT 0.0000 49.9200 0.0840 49.9440 ;
    END
  END m_hh[50]
  PIN m_hh[51]
    DIRECTION INPUT ;
    USE SIGNAL ;
    PORT
      LAYER M4 ;
        RECT 0.0000 50.7840 0.0840 50.8080 ;
    END
  END m_hh[51]
  PIN m_hh[52]
    DIRECTION INPUT ;
    USE SIGNAL ;
    PORT
      LAYER M4 ;
        RECT 0.0000 51.6480 0.0840 51.6720 ;
    END
  END m_hh[52]
  PIN m_hh[53]
    DIRECTION INPUT ;
    USE SIGNAL ;
    PORT
      LAYER M4 ;
        RECT 0.0000 52.5120 0.0840 52.5360 ;
    END
  END m_hh[53]
  PIN m_hh[54]
    DIRECTION INPUT ;
    USE SIGNAL ;
    PORT
      LAYER M4 ;
        RECT 0.0000 53.3760 0.0840 53.4000 ;
    END
  END m_hh[54]
  PIN m_hh[55]
    DIRECTION INPUT ;
    USE SIGNAL ;
    PORT
      LAYER M4 ;
        RECT 0.0000 54.2400 0.0840 54.2640 ;
    END
  END m_hh[55]
  PIN m_hh[56]
    DIRECTION INPUT ;
    USE SIGNAL ;
    PORT
      LAYER M4 ;
        RECT 0.0000 55.1040 0.0840 55.1280 ;
    END
  END m_hh[56]
  PIN m_hh[57]
    DIRECTION INPUT ;
    USE SIGNAL ;
    PORT
      LAYER M4 ;
        RECT 0.0000 55.9680 0.0840 55.9920 ;
    END
  END m_hh[57]
  PIN m_hh[58]
    DIRECTION INPUT ;
    USE SIGNAL ;
    PORT
      LAYER M4 ;
        RECT 0.0000 56.8320 0.0840 56.8560 ;
    END
  END m_hh[58]
  PIN m_hh[59]
    DIRECTION INPUT ;
    USE SIGNAL ;
    PORT
      LAYER M4 ;
        RECT 0.0000 57.6960 0.0840 57.7200 ;
    END
  END m_hh[59]
  PIN m_hh[5]
    DIRECTION INPUT ;
    USE SIGNAL ;
    PORT
      LAYER M4 ;
        RECT 0.0000 10.8480 0.0840 10.8720 ;
    END
  END m_hh[5]
  PIN m_hh[60]
    DIRECTION INPUT ;
    USE SIGNAL ;
    PORT
      LAYER M4 ;
        RECT 0.0000 58.5600 0.0840 58.5840 ;
    END
  END m_hh[60]
  PIN m_hh[61]
    DIRECTION INPUT ;
    USE SIGNAL ;
    PORT
      LAYER M4 ;
        RECT 0.0000 59.4240 0.0840 59.4480 ;
    END
  END m_hh[61]
  PIN m_hh[62]
    DIRECTION INPUT ;
    USE SIGNAL ;
    PORT
      LAYER M4 ;
        RECT 0.0000 60.2880 0.0840 60.3120 ;
    END
  END m_hh[62]
  PIN m_hh[63]
    DIRECTION INPUT ;
    USE SIGNAL ;
    PORT
      LAYER M4 ;
        RECT 0.0000 61.1520 0.0840 61.1760 ;
    END
  END m_hh[63]
  PIN m_hh[64]
    DIRECTION INPUT ;
    USE SIGNAL ;
    PORT
      LAYER M4 ;
        RECT 0.0000 62.0160 0.0840 62.0400 ;
    END
  END m_hh[64]
  PIN m_hh[65]
    DIRECTION INPUT ;
    USE SIGNAL ;
    PORT
      LAYER M4 ;
        RECT 0.0000 62.9760 0.0840 63.0000 ;
    END
  END m_hh[65]
  PIN m_hh[66]
    DIRECTION INPUT ;
    USE SIGNAL ;
    PORT
      LAYER M4 ;
        RECT 0.0000 63.8400 0.0840 63.8640 ;
    END
  END m_hh[66]
  PIN m_hh[67]
    DIRECTION INPUT ;
    USE SIGNAL ;
    PORT
      LAYER M4 ;
        RECT 0.0000 64.7040 0.0840 64.7280 ;
    END
  END m_hh[67]
  PIN m_hh[68]
    DIRECTION INPUT ;
    USE SIGNAL ;
    PORT
      LAYER M4 ;
        RECT 0.0000 65.5680 0.0840 65.5920 ;
    END
  END m_hh[68]
  PIN m_hh[69]
    DIRECTION INPUT ;
    USE SIGNAL ;
    PORT
      LAYER M4 ;
        RECT 0.0000 66.4320 0.0840 66.4560 ;
    END
  END m_hh[69]
  PIN m_hh[6]
    DIRECTION INPUT ;
    USE SIGNAL ;
    PORT
      LAYER M4 ;
        RECT 0.0000 11.7120 0.0840 11.7360 ;
    END
  END m_hh[6]
  PIN m_hh[70]
    DIRECTION INPUT ;
    USE SIGNAL ;
    PORT
      LAYER M4 ;
        RECT 0.0000 67.2960 0.0840 67.3200 ;
    END
  END m_hh[70]
  PIN m_hh[71]
    DIRECTION INPUT ;
    USE SIGNAL ;
    PORT
      LAYER M4 ;
        RECT 0.0000 68.1600 0.0840 68.1840 ;
    END
  END m_hh[71]
  PIN m_hh[72]
    DIRECTION INPUT ;
    USE SIGNAL ;
    PORT
      LAYER M4 ;
        RECT 0.0000 69.0240 0.0840 69.0480 ;
    END
  END m_hh[72]
  PIN m_hh[73]
    DIRECTION INPUT ;
    USE SIGNAL ;
    PORT
      LAYER M4 ;
        RECT 0.0000 69.8880 0.0840 69.9120 ;
    END
  END m_hh[73]
  PIN m_hh[74]
    DIRECTION INPUT ;
    USE SIGNAL ;
    PORT
      LAYER M4 ;
        RECT 0.0000 70.7520 0.0840 70.7760 ;
    END
  END m_hh[74]
  PIN m_hh[75]
    DIRECTION INPUT ;
    USE SIGNAL ;
    PORT
      LAYER M4 ;
        RECT 0.0000 71.6160 0.0840 71.6400 ;
    END
  END m_hh[75]
  PIN m_hh[76]
    DIRECTION INPUT ;
    USE SIGNAL ;
    PORT
      LAYER M4 ;
        RECT 0.0000 72.4800 0.0840 72.5040 ;
    END
  END m_hh[76]
  PIN m_hh[77]
    DIRECTION INPUT ;
    USE SIGNAL ;
    PORT
      LAYER M4 ;
        RECT 0.0000 73.3440 0.0840 73.3680 ;
    END
  END m_hh[77]
  PIN m_hh[78]
    DIRECTION INPUT ;
    USE SIGNAL ;
    PORT
      LAYER M4 ;
        RECT 0.0000 74.2080 0.0840 74.2320 ;
    END
  END m_hh[78]
  PIN m_hh[79]
    DIRECTION INPUT ;
    USE SIGNAL ;
    PORT
      LAYER M4 ;
        RECT 0.0000 75.0720 0.0840 75.0960 ;
    END
  END m_hh[79]
  PIN m_hh[7]
    DIRECTION INPUT ;
    USE SIGNAL ;
    PORT
      LAYER M4 ;
        RECT 0.0000 12.5760 0.0840 12.6000 ;
    END
  END m_hh[7]
  PIN m_hh[80]
    DIRECTION INPUT ;
    USE SIGNAL ;
    PORT
      LAYER M4 ;
        RECT 0.0000 75.9360 0.0840 75.9600 ;
    END
  END m_hh[80]
  PIN m_hh[81]
    DIRECTION INPUT ;
    USE SIGNAL ;
    PORT
      LAYER M4 ;
        RECT 0.0000 76.8000 0.0840 76.8240 ;
    END
  END m_hh[81]
  PIN m_hh[82]
    DIRECTION INPUT ;
    USE SIGNAL ;
    PORT
      LAYER M4 ;
        RECT 0.0000 77.6640 0.0840 77.6880 ;
    END
  END m_hh[82]
  PIN m_hh[83]
    DIRECTION INPUT ;
    USE SIGNAL ;
    PORT
      LAYER M4 ;
        RECT 0.0000 78.5280 0.0840 78.5520 ;
    END
  END m_hh[83]
  PIN m_hh[84]
    DIRECTION INPUT ;
    USE SIGNAL ;
    PORT
      LAYER M4 ;
        RECT 0.0000 79.3920 0.0840 79.4160 ;
    END
  END m_hh[84]
  PIN m_hh[85]
    DIRECTION INPUT ;
    USE SIGNAL ;
    PORT
      LAYER M4 ;
        RECT 0.0000 80.2560 0.0840 80.2800 ;
    END
  END m_hh[85]
  PIN m_hh[86]
    DIRECTION INPUT ;
    USE SIGNAL ;
    PORT
      LAYER M4 ;
        RECT 0.0000 81.1200 0.0840 81.1440 ;
    END
  END m_hh[86]
  PIN m_hh[87]
    DIRECTION INPUT ;
    USE SIGNAL ;
    PORT
      LAYER M4 ;
        RECT 0.0000 82.0800 0.0840 82.1040 ;
    END
  END m_hh[87]
  PIN m_hh[88]
    DIRECTION INPUT ;
    USE SIGNAL ;
    PORT
      LAYER M4 ;
        RECT 0.0000 82.9440 0.0840 82.9680 ;
    END
  END m_hh[88]
  PIN m_hh[89]
    DIRECTION INPUT ;
    USE SIGNAL ;
    PORT
      LAYER M4 ;
        RECT 0.0000 83.8080 0.0840 83.8320 ;
    END
  END m_hh[89]
  PIN m_hh[8]
    DIRECTION INPUT ;
    USE SIGNAL ;
    PORT
      LAYER M4 ;
        RECT 0.0000 13.4400 0.0840 13.4640 ;
    END
  END m_hh[8]
  PIN m_hh[90]
    DIRECTION INPUT ;
    USE SIGNAL ;
    PORT
      LAYER M4 ;
        RECT 0.0000 84.6720 0.0840 84.6960 ;
    END
  END m_hh[90]
  PIN m_hh[91]
    DIRECTION INPUT ;
    USE SIGNAL ;
    PORT
      LAYER M4 ;
        RECT 0.0000 85.5360 0.0840 85.5600 ;
    END
  END m_hh[91]
  PIN m_hh[92]
    DIRECTION INPUT ;
    USE SIGNAL ;
    PORT
      LAYER M4 ;
        RECT 0.0000 86.4000 0.0840 86.4240 ;
    END
  END m_hh[92]
  PIN m_hh[93]
    DIRECTION INPUT ;
    USE SIGNAL ;
    PORT
      LAYER M4 ;
        RECT 0.0000 87.2640 0.0840 87.2880 ;
    END
  END m_hh[93]
  PIN m_hh[94]
    DIRECTION INPUT ;
    USE SIGNAL ;
    PORT
      LAYER M4 ;
        RECT 0.0000 88.1280 0.0840 88.1520 ;
    END
  END m_hh[94]
  PIN m_hh[95]
    DIRECTION INPUT ;
    USE SIGNAL ;
    PORT
      LAYER M4 ;
        RECT 0.0000 88.9920 0.0840 89.0160 ;
    END
  END m_hh[95]
  PIN m_hh[96]
    DIRECTION INPUT ;
    USE SIGNAL ;
    PORT
      LAYER M4 ;
        RECT 0.0000 89.8560 0.0840 89.8800 ;
    END
  END m_hh[96]
  PIN m_hh[97]
    DIRECTION INPUT ;
    USE SIGNAL ;
    PORT
      LAYER M4 ;
        RECT 0.0000 90.7200 0.0840 90.7440 ;
    END
  END m_hh[97]
  PIN m_hh[98]
    DIRECTION INPUT ;
    USE SIGNAL ;
    PORT
      LAYER M4 ;
        RECT 0.0000 91.5840 0.0840 91.6080 ;
    END
  END m_hh[98]
  PIN m_hh[99]
    DIRECTION INPUT ;
    USE SIGNAL ;
    PORT
      LAYER M4 ;
        RECT 0.0000 92.4480 0.0840 92.4720 ;
    END
  END m_hh[99]
  PIN m_hh[9]
    DIRECTION INPUT ;
    USE SIGNAL ;
    PORT
      LAYER M4 ;
        RECT 0.0000 14.3040 0.0840 14.3280 ;
    END
  END m_hh[9]
  PIN m_kk[0]
    DIRECTION INPUT ;
    USE SIGNAL ;
    PORT
      LAYER M4 ;
        RECT 0.0000 117.6000 0.0840 117.6240 ;
    END
  END m_kk[0]
  PIN m_kk[100]
    DIRECTION INPUT ;
    USE SIGNAL ;
    PORT
      LAYER M4 ;
        RECT 0.0000 206.2080 0.0840 206.2320 ;
    END
  END m_kk[100]
  PIN m_kk[101]
    DIRECTION INPUT ;
    USE SIGNAL ;
    PORT
      LAYER M4 ;
        RECT 0.0000 207.0720 0.0840 207.0960 ;
    END
  END m_kk[101]
  PIN m_kk[102]
    DIRECTION INPUT ;
    USE SIGNAL ;
    PORT
      LAYER M4 ;
        RECT 0.0000 207.9360 0.0840 207.9600 ;
    END
  END m_kk[102]
  PIN m_kk[103]
    DIRECTION INPUT ;
    USE SIGNAL ;
    PORT
      LAYER M4 ;
        RECT 0.0000 208.8000 0.0840 208.8240 ;
    END
  END m_kk[103]
  PIN m_kk[104]
    DIRECTION INPUT ;
    USE SIGNAL ;
    PORT
      LAYER M4 ;
        RECT 0.0000 209.6640 0.0840 209.6880 ;
    END
  END m_kk[104]
  PIN m_kk[105]
    DIRECTION INPUT ;
    USE SIGNAL ;
    PORT
      LAYER M4 ;
        RECT 0.0000 210.5280 0.0840 210.5520 ;
    END
  END m_kk[105]
  PIN m_kk[106]
    DIRECTION INPUT ;
    USE SIGNAL ;
    PORT
      LAYER M4 ;
        RECT 0.0000 211.3920 0.0840 211.4160 ;
    END
  END m_kk[106]
  PIN m_kk[107]
    DIRECTION INPUT ;
    USE SIGNAL ;
    PORT
      LAYER M4 ;
        RECT 0.0000 212.2560 0.0840 212.2800 ;
    END
  END m_kk[107]
  PIN m_kk[108]
    DIRECTION INPUT ;
    USE SIGNAL ;
    PORT
      LAYER M4 ;
        RECT 0.0000 213.2160 0.0840 213.2400 ;
    END
  END m_kk[108]
  PIN m_kk[109]
    DIRECTION INPUT ;
    USE SIGNAL ;
    PORT
      LAYER M4 ;
        RECT 0.0000 214.0800 0.0840 214.1040 ;
    END
  END m_kk[109]
  PIN m_kk[10]
    DIRECTION INPUT ;
    USE SIGNAL ;
    PORT
      LAYER M4 ;
        RECT 0.0000 126.3360 0.0840 126.3600 ;
    END
  END m_kk[10]
  PIN m_kk[110]
    DIRECTION INPUT ;
    USE SIGNAL ;
    PORT
      LAYER M4 ;
        RECT 0.0000 214.9440 0.0840 214.9680 ;
    END
  END m_kk[110]
  PIN m_kk[111]
    DIRECTION INPUT ;
    USE SIGNAL ;
    PORT
      LAYER M4 ;
        RECT 0.0000 215.8080 0.0840 215.8320 ;
    END
  END m_kk[111]
  PIN m_kk[112]
    DIRECTION INPUT ;
    USE SIGNAL ;
    PORT
      LAYER M4 ;
        RECT 0.0000 216.6720 0.0840 216.6960 ;
    END
  END m_kk[112]
  PIN m_kk[113]
    DIRECTION INPUT ;
    USE SIGNAL ;
    PORT
      LAYER M4 ;
        RECT 0.0000 217.5360 0.0840 217.5600 ;
    END
  END m_kk[113]
  PIN m_kk[114]
    DIRECTION INPUT ;
    USE SIGNAL ;
    PORT
      LAYER M4 ;
        RECT 0.0000 218.4000 0.0840 218.4240 ;
    END
  END m_kk[114]
  PIN m_kk[115]
    DIRECTION INPUT ;
    USE SIGNAL ;
    PORT
      LAYER M4 ;
        RECT 0.0000 219.2640 0.0840 219.2880 ;
    END
  END m_kk[115]
  PIN m_kk[116]
    DIRECTION INPUT ;
    USE SIGNAL ;
    PORT
      LAYER M4 ;
        RECT 0.0000 220.1280 0.0840 220.1520 ;
    END
  END m_kk[116]
  PIN m_kk[117]
    DIRECTION INPUT ;
    USE SIGNAL ;
    PORT
      LAYER M4 ;
        RECT 0.0000 220.9920 0.0840 221.0160 ;
    END
  END m_kk[117]
  PIN m_kk[118]
    DIRECTION INPUT ;
    USE SIGNAL ;
    PORT
      LAYER M4 ;
        RECT 0.0000 221.8560 0.0840 221.8800 ;
    END
  END m_kk[118]
  PIN m_kk[119]
    DIRECTION INPUT ;
    USE SIGNAL ;
    PORT
      LAYER M4 ;
        RECT 0.0000 222.7200 0.0840 222.7440 ;
    END
  END m_kk[119]
  PIN m_kk[11]
    DIRECTION INPUT ;
    USE SIGNAL ;
    PORT
      LAYER M4 ;
        RECT 0.0000 127.2000 0.0840 127.2240 ;
    END
  END m_kk[11]
  PIN m_kk[120]
    DIRECTION INPUT ;
    USE SIGNAL ;
    PORT
      LAYER M4 ;
        RECT 0.0000 223.5840 0.0840 223.6080 ;
    END
  END m_kk[120]
  PIN m_kk[121]
    DIRECTION INPUT ;
    USE SIGNAL ;
    PORT
      LAYER M4 ;
        RECT 0.0000 224.4480 0.0840 224.4720 ;
    END
  END m_kk[121]
  PIN m_kk[122]
    DIRECTION INPUT ;
    USE SIGNAL ;
    PORT
      LAYER M4 ;
        RECT 0.0000 225.3120 0.0840 225.3360 ;
    END
  END m_kk[122]
  PIN m_kk[123]
    DIRECTION INPUT ;
    USE SIGNAL ;
    PORT
      LAYER M4 ;
        RECT 0.0000 226.1760 0.0840 226.2000 ;
    END
  END m_kk[123]
  PIN m_kk[124]
    DIRECTION INPUT ;
    USE SIGNAL ;
    PORT
      LAYER M4 ;
        RECT 0.0000 227.0400 0.0840 227.0640 ;
    END
  END m_kk[124]
  PIN m_kk[125]
    DIRECTION INPUT ;
    USE SIGNAL ;
    PORT
      LAYER M4 ;
        RECT 0.0000 227.9040 0.0840 227.9280 ;
    END
  END m_kk[125]
  PIN m_kk[126]
    DIRECTION INPUT ;
    USE SIGNAL ;
    PORT
      LAYER M4 ;
        RECT 0.0000 228.7680 0.0840 228.7920 ;
    END
  END m_kk[126]
  PIN m_kk[127]
    DIRECTION INPUT ;
    USE SIGNAL ;
    PORT
      LAYER M4 ;
        RECT 0.0000 229.6320 0.0840 229.6560 ;
    END
  END m_kk[127]
  PIN m_kk[12]
    DIRECTION INPUT ;
    USE SIGNAL ;
    PORT
      LAYER M4 ;
        RECT 0.0000 128.0640 0.0840 128.0880 ;
    END
  END m_kk[12]
  PIN m_kk[13]
    DIRECTION INPUT ;
    USE SIGNAL ;
    PORT
      LAYER M4 ;
        RECT 0.0000 128.9280 0.0840 128.9520 ;
    END
  END m_kk[13]
  PIN m_kk[14]
    DIRECTION INPUT ;
    USE SIGNAL ;
    PORT
      LAYER M4 ;
        RECT 0.0000 129.7920 0.0840 129.8160 ;
    END
  END m_kk[14]
  PIN m_kk[15]
    DIRECTION INPUT ;
    USE SIGNAL ;
    PORT
      LAYER M4 ;
        RECT 0.0000 130.6560 0.0840 130.6800 ;
    END
  END m_kk[15]
  PIN m_kk[16]
    DIRECTION INPUT ;
    USE SIGNAL ;
    PORT
      LAYER M4 ;
        RECT 0.0000 131.5200 0.0840 131.5440 ;
    END
  END m_kk[16]
  PIN m_kk[17]
    DIRECTION INPUT ;
    USE SIGNAL ;
    PORT
      LAYER M4 ;
        RECT 0.0000 132.3840 0.0840 132.4080 ;
    END
  END m_kk[17]
  PIN m_kk[18]
    DIRECTION INPUT ;
    USE SIGNAL ;
    PORT
      LAYER M4 ;
        RECT 0.0000 133.2480 0.0840 133.2720 ;
    END
  END m_kk[18]
  PIN m_kk[19]
    DIRECTION INPUT ;
    USE SIGNAL ;
    PORT
      LAYER M4 ;
        RECT 0.0000 134.1120 0.0840 134.1360 ;
    END
  END m_kk[19]
  PIN m_kk[1]
    DIRECTION INPUT ;
    USE SIGNAL ;
    PORT
      LAYER M4 ;
        RECT 0.0000 118.4640 0.0840 118.4880 ;
    END
  END m_kk[1]
  PIN m_kk[20]
    DIRECTION INPUT ;
    USE SIGNAL ;
    PORT
      LAYER M4 ;
        RECT 0.0000 134.9760 0.0840 135.0000 ;
    END
  END m_kk[20]
  PIN m_kk[21]
    DIRECTION INPUT ;
    USE SIGNAL ;
    PORT
      LAYER M4 ;
        RECT 0.0000 135.8400 0.0840 135.8640 ;
    END
  END m_kk[21]
  PIN m_kk[22]
    DIRECTION INPUT ;
    USE SIGNAL ;
    PORT
      LAYER M4 ;
        RECT 0.0000 136.7040 0.0840 136.7280 ;
    END
  END m_kk[22]
  PIN m_kk[23]
    DIRECTION INPUT ;
    USE SIGNAL ;
    PORT
      LAYER M4 ;
        RECT 0.0000 137.5680 0.0840 137.5920 ;
    END
  END m_kk[23]
  PIN m_kk[24]
    DIRECTION INPUT ;
    USE SIGNAL ;
    PORT
      LAYER M4 ;
        RECT 0.0000 138.5280 0.0840 138.5520 ;
    END
  END m_kk[24]
  PIN m_kk[25]
    DIRECTION INPUT ;
    USE SIGNAL ;
    PORT
      LAYER M4 ;
        RECT 0.0000 139.3920 0.0840 139.4160 ;
    END
  END m_kk[25]
  PIN m_kk[26]
    DIRECTION INPUT ;
    USE SIGNAL ;
    PORT
      LAYER M4 ;
        RECT 0.0000 140.2560 0.0840 140.2800 ;
    END
  END m_kk[26]
  PIN m_kk[27]
    DIRECTION INPUT ;
    USE SIGNAL ;
    PORT
      LAYER M4 ;
        RECT 0.0000 141.1200 0.0840 141.1440 ;
    END
  END m_kk[27]
  PIN m_kk[28]
    DIRECTION INPUT ;
    USE SIGNAL ;
    PORT
      LAYER M4 ;
        RECT 0.0000 141.9840 0.0840 142.0080 ;
    END
  END m_kk[28]
  PIN m_kk[29]
    DIRECTION INPUT ;
    USE SIGNAL ;
    PORT
      LAYER M4 ;
        RECT 0.0000 142.8480 0.0840 142.8720 ;
    END
  END m_kk[29]
  PIN m_kk[2]
    DIRECTION INPUT ;
    USE SIGNAL ;
    PORT
      LAYER M4 ;
        RECT 0.0000 119.4240 0.0840 119.4480 ;
    END
  END m_kk[2]
  PIN m_kk[30]
    DIRECTION INPUT ;
    USE SIGNAL ;
    PORT
      LAYER M4 ;
        RECT 0.0000 143.7120 0.0840 143.7360 ;
    END
  END m_kk[30]
  PIN m_kk[31]
    DIRECTION INPUT ;
    USE SIGNAL ;
    PORT
      LAYER M4 ;
        RECT 0.0000 144.5760 0.0840 144.6000 ;
    END
  END m_kk[31]
  PIN m_kk[32]
    DIRECTION INPUT ;
    USE SIGNAL ;
    PORT
      LAYER M4 ;
        RECT 0.0000 145.4400 0.0840 145.4640 ;
    END
  END m_kk[32]
  PIN m_kk[33]
    DIRECTION INPUT ;
    USE SIGNAL ;
    PORT
      LAYER M4 ;
        RECT 0.0000 146.3040 0.0840 146.3280 ;
    END
  END m_kk[33]
  PIN m_kk[34]
    DIRECTION INPUT ;
    USE SIGNAL ;
    PORT
      LAYER M4 ;
        RECT 0.0000 147.1680 0.0840 147.1920 ;
    END
  END m_kk[34]
  PIN m_kk[35]
    DIRECTION INPUT ;
    USE SIGNAL ;
    PORT
      LAYER M4 ;
        RECT 0.0000 148.0320 0.0840 148.0560 ;
    END
  END m_kk[35]
  PIN m_kk[36]
    DIRECTION INPUT ;
    USE SIGNAL ;
    PORT
      LAYER M4 ;
        RECT 0.0000 148.8960 0.0840 148.9200 ;
    END
  END m_kk[36]
  PIN m_kk[37]
    DIRECTION INPUT ;
    USE SIGNAL ;
    PORT
      LAYER M4 ;
        RECT 0.0000 149.7600 0.0840 149.7840 ;
    END
  END m_kk[37]
  PIN m_kk[38]
    DIRECTION INPUT ;
    USE SIGNAL ;
    PORT
      LAYER M4 ;
        RECT 0.0000 150.6240 0.0840 150.6480 ;
    END
  END m_kk[38]
  PIN m_kk[39]
    DIRECTION INPUT ;
    USE SIGNAL ;
    PORT
      LAYER M4 ;
        RECT 0.0000 151.4880 0.0840 151.5120 ;
    END
  END m_kk[39]
  PIN m_kk[3]
    DIRECTION INPUT ;
    USE SIGNAL ;
    PORT
      LAYER M4 ;
        RECT 0.0000 120.2880 0.0840 120.3120 ;
    END
  END m_kk[3]
  PIN m_kk[40]
    DIRECTION INPUT ;
    USE SIGNAL ;
    PORT
      LAYER M4 ;
        RECT 0.0000 152.3520 0.0840 152.3760 ;
    END
  END m_kk[40]
  PIN m_kk[41]
    DIRECTION INPUT ;
    USE SIGNAL ;
    PORT
      LAYER M4 ;
        RECT 0.0000 153.2160 0.0840 153.2400 ;
    END
  END m_kk[41]
  PIN m_kk[42]
    DIRECTION INPUT ;
    USE SIGNAL ;
    PORT
      LAYER M4 ;
        RECT 0.0000 154.0800 0.0840 154.1040 ;
    END
  END m_kk[42]
  PIN m_kk[43]
    DIRECTION INPUT ;
    USE SIGNAL ;
    PORT
      LAYER M4 ;
        RECT 0.0000 154.9440 0.0840 154.9680 ;
    END
  END m_kk[43]
  PIN m_kk[44]
    DIRECTION INPUT ;
    USE SIGNAL ;
    PORT
      LAYER M4 ;
        RECT 0.0000 155.8080 0.0840 155.8320 ;
    END
  END m_kk[44]
  PIN m_kk[45]
    DIRECTION INPUT ;
    USE SIGNAL ;
    PORT
      LAYER M4 ;
        RECT 0.0000 156.7680 0.0840 156.7920 ;
    END
  END m_kk[45]
  PIN m_kk[46]
    DIRECTION INPUT ;
    USE SIGNAL ;
    PORT
      LAYER M4 ;
        RECT 0.0000 157.6320 0.0840 157.6560 ;
    END
  END m_kk[46]
  PIN m_kk[47]
    DIRECTION INPUT ;
    USE SIGNAL ;
    PORT
      LAYER M4 ;
        RECT 0.0000 158.4960 0.0840 158.5200 ;
    END
  END m_kk[47]
  PIN m_kk[48]
    DIRECTION INPUT ;
    USE SIGNAL ;
    PORT
      LAYER M4 ;
        RECT 0.0000 159.3600 0.0840 159.3840 ;
    END
  END m_kk[48]
  PIN m_kk[49]
    DIRECTION INPUT ;
    USE SIGNAL ;
    PORT
      LAYER M4 ;
        RECT 0.0000 160.2240 0.0840 160.2480 ;
    END
  END m_kk[49]
  PIN m_kk[4]
    DIRECTION INPUT ;
    USE SIGNAL ;
    PORT
      LAYER M4 ;
        RECT 0.0000 121.1520 0.0840 121.1760 ;
    END
  END m_kk[4]
  PIN m_kk[50]
    DIRECTION INPUT ;
    USE SIGNAL ;
    PORT
      LAYER M4 ;
        RECT 0.0000 161.0880 0.0840 161.1120 ;
    END
  END m_kk[50]
  PIN m_kk[51]
    DIRECTION INPUT ;
    USE SIGNAL ;
    PORT
      LAYER M4 ;
        RECT 0.0000 161.9520 0.0840 161.9760 ;
    END
  END m_kk[51]
  PIN m_kk[52]
    DIRECTION INPUT ;
    USE SIGNAL ;
    PORT
      LAYER M4 ;
        RECT 0.0000 162.8160 0.0840 162.8400 ;
    END
  END m_kk[52]
  PIN m_kk[53]
    DIRECTION INPUT ;
    USE SIGNAL ;
    PORT
      LAYER M4 ;
        RECT 0.0000 163.6800 0.0840 163.7040 ;
    END
  END m_kk[53]
  PIN m_kk[54]
    DIRECTION INPUT ;
    USE SIGNAL ;
    PORT
      LAYER M4 ;
        RECT 0.0000 164.5440 0.0840 164.5680 ;
    END
  END m_kk[54]
  PIN m_kk[55]
    DIRECTION INPUT ;
    USE SIGNAL ;
    PORT
      LAYER M4 ;
        RECT 0.0000 165.4080 0.0840 165.4320 ;
    END
  END m_kk[55]
  PIN m_kk[56]
    DIRECTION INPUT ;
    USE SIGNAL ;
    PORT
      LAYER M4 ;
        RECT 0.0000 166.2720 0.0840 166.2960 ;
    END
  END m_kk[56]
  PIN m_kk[57]
    DIRECTION INPUT ;
    USE SIGNAL ;
    PORT
      LAYER M4 ;
        RECT 0.0000 167.1360 0.0840 167.1600 ;
    END
  END m_kk[57]
  PIN m_kk[58]
    DIRECTION INPUT ;
    USE SIGNAL ;
    PORT
      LAYER M4 ;
        RECT 0.0000 168.0000 0.0840 168.0240 ;
    END
  END m_kk[58]
  PIN m_kk[59]
    DIRECTION INPUT ;
    USE SIGNAL ;
    PORT
      LAYER M4 ;
        RECT 0.0000 168.8640 0.0840 168.8880 ;
    END
  END m_kk[59]
  PIN m_kk[5]
    DIRECTION INPUT ;
    USE SIGNAL ;
    PORT
      LAYER M4 ;
        RECT 0.0000 122.0160 0.0840 122.0400 ;
    END
  END m_kk[5]
  PIN m_kk[60]
    DIRECTION INPUT ;
    USE SIGNAL ;
    PORT
      LAYER M4 ;
        RECT 0.0000 169.7280 0.0840 169.7520 ;
    END
  END m_kk[60]
  PIN m_kk[61]
    DIRECTION INPUT ;
    USE SIGNAL ;
    PORT
      LAYER M4 ;
        RECT 0.0000 170.5920 0.0840 170.6160 ;
    END
  END m_kk[61]
  PIN m_kk[62]
    DIRECTION INPUT ;
    USE SIGNAL ;
    PORT
      LAYER M4 ;
        RECT 0.0000 171.4560 0.0840 171.4800 ;
    END
  END m_kk[62]
  PIN m_kk[63]
    DIRECTION INPUT ;
    USE SIGNAL ;
    PORT
      LAYER M4 ;
        RECT 0.0000 174.0480 0.0840 174.0720 ;
    END
  END m_kk[63]
  PIN m_kk[64]
    DIRECTION INPUT ;
    USE SIGNAL ;
    PORT
      LAYER M4 ;
        RECT 0.0000 174.9120 0.0840 174.9360 ;
    END
  END m_kk[64]
  PIN m_kk[65]
    DIRECTION INPUT ;
    USE SIGNAL ;
    PORT
      LAYER M4 ;
        RECT 0.0000 175.8720 0.0840 175.8960 ;
    END
  END m_kk[65]
  PIN m_kk[66]
    DIRECTION INPUT ;
    USE SIGNAL ;
    PORT
      LAYER M4 ;
        RECT 0.0000 176.7360 0.0840 176.7600 ;
    END
  END m_kk[66]
  PIN m_kk[67]
    DIRECTION INPUT ;
    USE SIGNAL ;
    PORT
      LAYER M4 ;
        RECT 0.0000 177.6000 0.0840 177.6240 ;
    END
  END m_kk[67]
  PIN m_kk[68]
    DIRECTION INPUT ;
    USE SIGNAL ;
    PORT
      LAYER M4 ;
        RECT 0.0000 178.4640 0.0840 178.4880 ;
    END
  END m_kk[68]
  PIN m_kk[69]
    DIRECTION INPUT ;
    USE SIGNAL ;
    PORT
      LAYER M4 ;
        RECT 0.0000 179.3280 0.0840 179.3520 ;
    END
  END m_kk[69]
  PIN m_kk[6]
    DIRECTION INPUT ;
    USE SIGNAL ;
    PORT
      LAYER M4 ;
        RECT 0.0000 122.8800 0.0840 122.9040 ;
    END
  END m_kk[6]
  PIN m_kk[70]
    DIRECTION INPUT ;
    USE SIGNAL ;
    PORT
      LAYER M4 ;
        RECT 0.0000 180.1920 0.0840 180.2160 ;
    END
  END m_kk[70]
  PIN m_kk[71]
    DIRECTION INPUT ;
    USE SIGNAL ;
    PORT
      LAYER M4 ;
        RECT 0.0000 181.0560 0.0840 181.0800 ;
    END
  END m_kk[71]
  PIN m_kk[72]
    DIRECTION INPUT ;
    USE SIGNAL ;
    PORT
      LAYER M4 ;
        RECT 0.0000 181.9200 0.0840 181.9440 ;
    END
  END m_kk[72]
  PIN m_kk[73]
    DIRECTION INPUT ;
    USE SIGNAL ;
    PORT
      LAYER M4 ;
        RECT 0.0000 182.7840 0.0840 182.8080 ;
    END
  END m_kk[73]
  PIN m_kk[74]
    DIRECTION INPUT ;
    USE SIGNAL ;
    PORT
      LAYER M4 ;
        RECT 0.0000 183.6480 0.0840 183.6720 ;
    END
  END m_kk[74]
  PIN m_kk[75]
    DIRECTION INPUT ;
    USE SIGNAL ;
    PORT
      LAYER M4 ;
        RECT 0.0000 184.5120 0.0840 184.5360 ;
    END
  END m_kk[75]
  PIN m_kk[76]
    DIRECTION INPUT ;
    USE SIGNAL ;
    PORT
      LAYER M4 ;
        RECT 0.0000 185.3760 0.0840 185.4000 ;
    END
  END m_kk[76]
  PIN m_kk[77]
    DIRECTION INPUT ;
    USE SIGNAL ;
    PORT
      LAYER M4 ;
        RECT 0.0000 186.2400 0.0840 186.2640 ;
    END
  END m_kk[77]
  PIN m_kk[78]
    DIRECTION INPUT ;
    USE SIGNAL ;
    PORT
      LAYER M4 ;
        RECT 0.0000 187.1040 0.0840 187.1280 ;
    END
  END m_kk[78]
  PIN m_kk[79]
    DIRECTION INPUT ;
    USE SIGNAL ;
    PORT
      LAYER M4 ;
        RECT 0.0000 187.9680 0.0840 187.9920 ;
    END
  END m_kk[79]
  PIN m_kk[7]
    DIRECTION INPUT ;
    USE SIGNAL ;
    PORT
      LAYER M4 ;
        RECT 0.0000 123.7440 0.0840 123.7680 ;
    END
  END m_kk[7]
  PIN m_kk[80]
    DIRECTION INPUT ;
    USE SIGNAL ;
    PORT
      LAYER M4 ;
        RECT 0.0000 188.8320 0.0840 188.8560 ;
    END
  END m_kk[80]
  PIN m_kk[81]
    DIRECTION INPUT ;
    USE SIGNAL ;
    PORT
      LAYER M4 ;
        RECT 0.0000 189.6960 0.0840 189.7200 ;
    END
  END m_kk[81]
  PIN m_kk[82]
    DIRECTION INPUT ;
    USE SIGNAL ;
    PORT
      LAYER M4 ;
        RECT 0.0000 190.5600 0.0840 190.5840 ;
    END
  END m_kk[82]
  PIN m_kk[83]
    DIRECTION INPUT ;
    USE SIGNAL ;
    PORT
      LAYER M4 ;
        RECT 0.0000 191.4240 0.0840 191.4480 ;
    END
  END m_kk[83]
  PIN m_kk[84]
    DIRECTION INPUT ;
    USE SIGNAL ;
    PORT
      LAYER M4 ;
        RECT 0.0000 192.2880 0.0840 192.3120 ;
    END
  END m_kk[84]
  PIN m_kk[85]
    DIRECTION INPUT ;
    USE SIGNAL ;
    PORT
      LAYER M4 ;
        RECT 0.0000 193.1520 0.0840 193.1760 ;
    END
  END m_kk[85]
  PIN m_kk[86]
    DIRECTION INPUT ;
    USE SIGNAL ;
    PORT
      LAYER M4 ;
        RECT 0.0000 194.1120 0.0840 194.1360 ;
    END
  END m_kk[86]
  PIN m_kk[87]
    DIRECTION INPUT ;
    USE SIGNAL ;
    PORT
      LAYER M4 ;
        RECT 0.0000 194.9760 0.0840 195.0000 ;
    END
  END m_kk[87]
  PIN m_kk[88]
    DIRECTION INPUT ;
    USE SIGNAL ;
    PORT
      LAYER M4 ;
        RECT 0.0000 195.8400 0.0840 195.8640 ;
    END
  END m_kk[88]
  PIN m_kk[89]
    DIRECTION INPUT ;
    USE SIGNAL ;
    PORT
      LAYER M4 ;
        RECT 0.0000 196.7040 0.0840 196.7280 ;
    END
  END m_kk[89]
  PIN m_kk[8]
    DIRECTION INPUT ;
    USE SIGNAL ;
    PORT
      LAYER M4 ;
        RECT 0.0000 124.6080 0.0840 124.6320 ;
    END
  END m_kk[8]
  PIN m_kk[90]
    DIRECTION INPUT ;
    USE SIGNAL ;
    PORT
      LAYER M4 ;
        RECT 0.0000 197.5680 0.0840 197.5920 ;
    END
  END m_kk[90]
  PIN m_kk[91]
    DIRECTION INPUT ;
    USE SIGNAL ;
    PORT
      LAYER M4 ;
        RECT 0.0000 198.4320 0.0840 198.4560 ;
    END
  END m_kk[91]
  PIN m_kk[92]
    DIRECTION INPUT ;
    USE SIGNAL ;
    PORT
      LAYER M4 ;
        RECT 0.0000 199.2960 0.0840 199.3200 ;
    END
  END m_kk[92]
  PIN m_kk[93]
    DIRECTION INPUT ;
    USE SIGNAL ;
    PORT
      LAYER M4 ;
        RECT 0.0000 200.1600 0.0840 200.1840 ;
    END
  END m_kk[93]
  PIN m_kk[94]
    DIRECTION INPUT ;
    USE SIGNAL ;
    PORT
      LAYER M4 ;
        RECT 0.0000 201.0240 0.0840 201.0480 ;
    END
  END m_kk[94]
  PIN m_kk[95]
    DIRECTION INPUT ;
    USE SIGNAL ;
    PORT
      LAYER M4 ;
        RECT 0.0000 201.8880 0.0840 201.9120 ;
    END
  END m_kk[95]
  PIN m_kk[96]
    DIRECTION INPUT ;
    USE SIGNAL ;
    PORT
      LAYER M4 ;
        RECT 0.0000 202.7520 0.0840 202.7760 ;
    END
  END m_kk[96]
  PIN m_kk[97]
    DIRECTION INPUT ;
    USE SIGNAL ;
    PORT
      LAYER M4 ;
        RECT 0.0000 203.6160 0.0840 203.6400 ;
    END
  END m_kk[97]
  PIN m_kk[98]
    DIRECTION INPUT ;
    USE SIGNAL ;
    PORT
      LAYER M4 ;
        RECT 0.0000 204.4800 0.0840 204.5040 ;
    END
  END m_kk[98]
  PIN m_kk[99]
    DIRECTION INPUT ;
    USE SIGNAL ;
    PORT
      LAYER M4 ;
        RECT 0.0000 205.3440 0.0840 205.3680 ;
    END
  END m_kk[99]
  PIN m_kk[9]
    DIRECTION INPUT ;
    USE SIGNAL ;
    PORT
      LAYER M4 ;
        RECT 0.0000 125.4720 0.0840 125.4960 ;
    END
  END m_kk[9]
  PIN m_pre
    DIRECTION INPUT ;
    USE SIGNAL ;
    PORT
      LAYER M4 ;
        RECT 0.0000 5.5680 0.0840 5.5920 ;
    END
  END m_pre
  PIN m_v
    DIRECTION INPUT ;
    USE SIGNAL ;
    PORT
      LAYER M4 ;
        RECT 0.0000 4.7040 0.0840 4.7280 ;
    END
  END m_v
  PIN p_c[0]
    DIRECTION OUTPUT ;
    USE SIGNAL ;
    PORT
      LAYER M3 ;
        RECT 157.4640 0.0000 157.4820 0.0380 ;
    END
  END p_c[0]
  PIN p_c[1]
    DIRECTION OUTPUT ;
    USE SIGNAL ;
    PORT
      LAYER M5 ;
        RECT 155.9040 0.0000 155.9280 0.0840 ;
    END
  END p_c[1]
  PIN p_dd[0]
    DIRECTION OUTPUT ;
    USE SIGNAL ;
    PORT
      LAYER M3 ;
        RECT 54.8640 0.0000 54.8820 0.0380 ;
    END
  END p_dd[0]
  PIN p_dd[10]
    DIRECTION OUTPUT ;
    USE SIGNAL ;
    PORT
      LAYER M3 ;
        RECT 39.3120 0.0000 39.3300 0.0380 ;
    END
  END p_dd[10]
  PIN p_dd[11]
    DIRECTION OUTPUT ;
    USE SIGNAL ;
    PORT
      LAYER M5 ;
        RECT 37.7280 0.0000 37.7520 0.0840 ;
    END
  END p_dd[11]
  PIN p_dd[12]
    DIRECTION OUTPUT ;
    USE SIGNAL ;
    PORT
      LAYER M3 ;
        RECT 36.2160 0.0000 36.2340 0.0380 ;
    END
  END p_dd[12]
  PIN p_dd[13]
    DIRECTION OUTPUT ;
    USE SIGNAL ;
    PORT
      LAYER M5 ;
        RECT 34.6560 0.0000 34.6800 0.0840 ;
    END
  END p_dd[13]
  PIN p_dd[14]
    DIRECTION OUTPUT ;
    USE SIGNAL ;
    PORT
      LAYER M3 ;
        RECT 33.0480 0.0000 33.0660 0.0380 ;
    END
  END p_dd[14]
  PIN p_dd[15]
    DIRECTION OUTPUT ;
    USE SIGNAL ;
    PORT
      LAYER M5 ;
        RECT 31.4880 0.0000 31.5120 0.0840 ;
    END
  END p_dd[15]
  PIN p_dd[16]
    DIRECTION OUTPUT ;
    USE SIGNAL ;
    PORT
      LAYER M3 ;
        RECT 29.9520 0.0000 29.9700 0.0380 ;
    END
  END p_dd[16]
  PIN p_dd[17]
    DIRECTION OUTPUT ;
    USE SIGNAL ;
    PORT
      LAYER M5 ;
        RECT 28.4160 0.0000 28.4400 0.0840 ;
    END
  END p_dd[17]
  PIN p_dd[18]
    DIRECTION OUTPUT ;
    USE SIGNAL ;
    PORT
      LAYER M3 ;
        RECT 26.8560 0.0000 26.8740 0.0380 ;
    END
  END p_dd[18]
  PIN p_dd[19]
    DIRECTION OUTPUT ;
    USE SIGNAL ;
    PORT
      LAYER M5 ;
        RECT 25.3440 0.0000 25.3680 0.0840 ;
    END
  END p_dd[19]
  PIN p_dd[1]
    DIRECTION OUTPUT ;
    USE SIGNAL ;
    PORT
      LAYER M5 ;
        RECT 53.2800 0.0000 53.3040 0.0840 ;
    END
  END p_dd[1]
  PIN p_dd[20]
    DIRECTION OUTPUT ;
    USE SIGNAL ;
    PORT
      LAYER M3 ;
        RECT 23.7600 0.0000 23.7780 0.0380 ;
    END
  END p_dd[20]
  PIN p_dd[21]
    DIRECTION OUTPUT ;
    USE SIGNAL ;
    PORT
      LAYER M5 ;
        RECT 22.1760 0.0000 22.2000 0.0840 ;
    END
  END p_dd[21]
  PIN p_dd[22]
    DIRECTION OUTPUT ;
    USE SIGNAL ;
    PORT
      LAYER M3 ;
        RECT 20.6640 0.0000 20.6820 0.0380 ;
    END
  END p_dd[22]
  PIN p_dd[23]
    DIRECTION OUTPUT ;
    USE SIGNAL ;
    PORT
      LAYER M5 ;
        RECT 19.1040 0.0000 19.1280 0.0840 ;
    END
  END p_dd[23]
  PIN p_dd[24]
    DIRECTION OUTPUT ;
    USE SIGNAL ;
    PORT
      LAYER M3 ;
        RECT 17.4960 0.0000 17.5140 0.0380 ;
    END
  END p_dd[24]
  PIN p_dd[25]
    DIRECTION OUTPUT ;
    USE SIGNAL ;
    PORT
      LAYER M5 ;
        RECT 15.9360 0.0000 15.9600 0.0840 ;
    END
  END p_dd[25]
  PIN p_dd[26]
    DIRECTION OUTPUT ;
    USE SIGNAL ;
    PORT
      LAYER M3 ;
        RECT 14.4000 0.0000 14.4180 0.0380 ;
    END
  END p_dd[26]
  PIN p_dd[27]
    DIRECTION OUTPUT ;
    USE SIGNAL ;
    PORT
      LAYER M5 ;
        RECT 12.8640 0.0000 12.8880 0.0840 ;
    END
  END p_dd[27]
  PIN p_dd[28]
    DIRECTION OUTPUT ;
    USE SIGNAL ;
    PORT
      LAYER M3 ;
        RECT 11.3040 0.0000 11.3220 0.0380 ;
    END
  END p_dd[28]
  PIN p_dd[29]
    DIRECTION OUTPUT ;
    USE SIGNAL ;
    PORT
      LAYER M5 ;
        RECT 9.7920 0.0000 9.8160 0.0840 ;
    END
  END p_dd[29]
  PIN p_dd[2]
    DIRECTION OUTPUT ;
    USE SIGNAL ;
    PORT
      LAYER M3 ;
        RECT 51.7680 0.0000 51.7860 0.0380 ;
    END
  END p_dd[2]
  PIN p_dd[30]
    DIRECTION OUTPUT ;
    USE SIGNAL ;
    PORT
      LAYER M3 ;
        RECT 8.2080 0.0000 8.2260 0.0380 ;
    END
  END p_dd[30]
  PIN p_dd[31]
    DIRECTION OUTPUT ;
    USE SIGNAL ;
    PORT
      LAYER M5 ;
        RECT 6.6240 0.0000 6.6480 0.0840 ;
    END
  END p_dd[31]
  PIN p_dd[3]
    DIRECTION OUTPUT ;
    USE SIGNAL ;
    PORT
      LAYER M5 ;
        RECT 50.2080 0.0000 50.2320 0.0840 ;
    END
  END p_dd[3]
  PIN p_dd[4]
    DIRECTION OUTPUT ;
    USE SIGNAL ;
    PORT
      LAYER M3 ;
        RECT 48.6000 0.0000 48.6180 0.0380 ;
    END
  END p_dd[4]
  PIN p_dd[5]
    DIRECTION OUTPUT ;
    USE SIGNAL ;
    PORT
      LAYER M5 ;
        RECT 47.0400 0.0000 47.0640 0.0840 ;
    END
  END p_dd[5]
  PIN p_dd[6]
    DIRECTION OUTPUT ;
    USE SIGNAL ;
    PORT
      LAYER M3 ;
        RECT 45.5040 0.0000 45.5220 0.0380 ;
    END
  END p_dd[6]
  PIN p_dd[7]
    DIRECTION OUTPUT ;
    USE SIGNAL ;
    PORT
      LAYER M5 ;
        RECT 43.9680 0.0000 43.9920 0.0840 ;
    END
  END p_dd[7]
  PIN p_dd[8]
    DIRECTION OUTPUT ;
    USE SIGNAL ;
    PORT
      LAYER M3 ;
        RECT 42.4080 0.0000 42.4260 0.0380 ;
    END
  END p_dd[8]
  PIN p_dd[9]
    DIRECTION OUTPUT ;
    USE SIGNAL ;
    PORT
      LAYER M5 ;
        RECT 40.8960 0.0000 40.9200 0.0840 ;
    END
  END p_dd[9]
  PIN p_hh[0]
    DIRECTION OUTPUT ;
    USE SIGNAL ;
    PORT
      LAYER M3 ;
        RECT 154.3680 0.0000 154.3860 0.0380 ;
    END
  END p_hh[0]
  PIN p_hh[10]
    DIRECTION OUTPUT ;
    USE SIGNAL ;
    PORT
      LAYER M3 ;
        RECT 138.8160 0.0000 138.8340 0.0380 ;
    END
  END p_hh[10]
  PIN p_hh[11]
    DIRECTION OUTPUT ;
    USE SIGNAL ;
    PORT
      LAYER M5 ;
        RECT 137.2800 0.0000 137.3040 0.0840 ;
    END
  END p_hh[11]
  PIN p_hh[12]
    DIRECTION OUTPUT ;
    USE SIGNAL ;
    PORT
      LAYER M3 ;
        RECT 135.7200 0.0000 135.7380 0.0380 ;
    END
  END p_hh[12]
  PIN p_hh[13]
    DIRECTION OUTPUT ;
    USE SIGNAL ;
    PORT
      LAYER M5 ;
        RECT 134.2080 0.0000 134.2320 0.0840 ;
    END
  END p_hh[13]
  PIN p_hh[14]
    DIRECTION OUTPUT ;
    USE SIGNAL ;
    PORT
      LAYER M3 ;
        RECT 132.6240 0.0000 132.6420 0.0380 ;
    END
  END p_hh[14]
  PIN p_hh[15]
    DIRECTION OUTPUT ;
    USE SIGNAL ;
    PORT
      LAYER M5 ;
        RECT 131.0400 0.0000 131.0640 0.0840 ;
    END
  END p_hh[15]
  PIN p_hh[16]
    DIRECTION OUTPUT ;
    USE SIGNAL ;
    PORT
      LAYER M3 ;
        RECT 129.5280 0.0000 129.5460 0.0380 ;
    END
  END p_hh[16]
  PIN p_hh[17]
    DIRECTION OUTPUT ;
    USE SIGNAL ;
    PORT
      LAYER M5 ;
        RECT 127.9680 0.0000 127.9920 0.0840 ;
    END
  END p_hh[17]
  PIN p_hh[18]
    DIRECTION OUTPUT ;
    USE SIGNAL ;
    PORT
      LAYER M3 ;
        RECT 126.3600 0.0000 126.3780 0.0380 ;
    END
  END p_hh[18]
  PIN p_hh[19]
    DIRECTION OUTPUT ;
    USE SIGNAL ;
    PORT
      LAYER M5 ;
        RECT 124.8000 0.0000 124.8240 0.0840 ;
    END
  END p_hh[19]
  PIN p_hh[1]
    DIRECTION OUTPUT ;
    USE SIGNAL ;
    PORT
      LAYER M5 ;
        RECT 152.8320 0.0000 152.8560 0.0840 ;
    END
  END p_hh[1]
  PIN p_hh[20]
    DIRECTION OUTPUT ;
    USE SIGNAL ;
    PORT
      LAYER M3 ;
        RECT 123.2640 0.0000 123.2820 0.0380 ;
    END
  END p_hh[20]
  PIN p_hh[21]
    DIRECTION OUTPUT ;
    USE SIGNAL ;
    PORT
      LAYER M5 ;
        RECT 121.7280 0.0000 121.7520 0.0840 ;
    END
  END p_hh[21]
  PIN p_hh[22]
    DIRECTION OUTPUT ;
    USE SIGNAL ;
    PORT
      LAYER M3 ;
        RECT 120.1680 0.0000 120.1860 0.0380 ;
    END
  END p_hh[22]
  PIN p_hh[23]
    DIRECTION OUTPUT ;
    USE SIGNAL ;
    PORT
      LAYER M5 ;
        RECT 118.6560 0.0000 118.6800 0.0840 ;
    END
  END p_hh[23]
  PIN p_hh[24]
    DIRECTION OUTPUT ;
    USE SIGNAL ;
    PORT
      LAYER M3 ;
        RECT 117.0720 0.0000 117.0900 0.0380 ;
    END
  END p_hh[24]
  PIN p_hh[25]
    DIRECTION OUTPUT ;
    USE SIGNAL ;
    PORT
      LAYER M5 ;
        RECT 115.4880 0.0000 115.5120 0.0840 ;
    END
  END p_hh[25]
  PIN p_hh[26]
    DIRECTION OUTPUT ;
    USE SIGNAL ;
    PORT
      LAYER M3 ;
        RECT 113.9760 0.0000 113.9940 0.0380 ;
    END
  END p_hh[26]
  PIN p_hh[27]
    DIRECTION OUTPUT ;
    USE SIGNAL ;
    PORT
      LAYER M5 ;
        RECT 112.4160 0.0000 112.4400 0.0840 ;
    END
  END p_hh[27]
  PIN p_hh[28]
    DIRECTION OUTPUT ;
    USE SIGNAL ;
    PORT
      LAYER M3 ;
        RECT 110.8080 0.0000 110.8260 0.0380 ;
    END
  END p_hh[28]
  PIN p_hh[29]
    DIRECTION OUTPUT ;
    USE SIGNAL ;
    PORT
      LAYER M5 ;
        RECT 109.2480 0.0000 109.2720 0.0840 ;
    END
  END p_hh[29]
  PIN p_hh[2]
    DIRECTION OUTPUT ;
    USE SIGNAL ;
    PORT
      LAYER M3 ;
        RECT 151.2720 0.0000 151.2900 0.0380 ;
    END
  END p_hh[2]
  PIN p_hh[30]
    DIRECTION OUTPUT ;
    USE SIGNAL ;
    PORT
      LAYER M3 ;
        RECT 107.7120 0.0000 107.7300 0.0380 ;
    END
  END p_hh[30]
  PIN p_hh[31]
    DIRECTION OUTPUT ;
    USE SIGNAL ;
    PORT
      LAYER M5 ;
        RECT 106.1760 0.0000 106.2000 0.0840 ;
    END
  END p_hh[31]
  PIN p_hh[3]
    DIRECTION OUTPUT ;
    USE SIGNAL ;
    PORT
      LAYER M5 ;
        RECT 149.7600 0.0000 149.7840 0.0840 ;
    END
  END p_hh[3]
  PIN p_hh[4]
    DIRECTION OUTPUT ;
    USE SIGNAL ;
    PORT
      LAYER M3 ;
        RECT 148.1760 0.0000 148.1940 0.0380 ;
    END
  END p_hh[4]
  PIN p_hh[5]
    DIRECTION OUTPUT ;
    USE SIGNAL ;
    PORT
      LAYER M5 ;
        RECT 146.5920 0.0000 146.6160 0.0840 ;
    END
  END p_hh[5]
  PIN p_hh[6]
    DIRECTION OUTPUT ;
    USE SIGNAL ;
    PORT
      LAYER M3 ;
        RECT 145.0800 0.0000 145.0980 0.0380 ;
    END
  END p_hh[6]
  PIN p_hh[7]
    DIRECTION OUTPUT ;
    USE SIGNAL ;
    PORT
      LAYER M5 ;
        RECT 143.5200 0.0000 143.5440 0.0840 ;
    END
  END p_hh[7]
  PIN p_hh[8]
    DIRECTION OUTPUT ;
    USE SIGNAL ;
    PORT
      LAYER M3 ;
        RECT 141.9120 0.0000 141.9300 0.0380 ;
    END
  END p_hh[8]
  PIN p_hh[9]
    DIRECTION OUTPUT ;
    USE SIGNAL ;
    PORT
      LAYER M5 ;
        RECT 140.3520 0.0000 140.3760 0.0840 ;
    END
  END p_hh[9]
  PIN p_kk[0]
    DIRECTION OUTPUT ;
    USE SIGNAL ;
    PORT
      LAYER M3 ;
        RECT 104.6160 0.0000 104.6340 0.0380 ;
    END
  END p_kk[0]
  PIN p_kk[10]
    DIRECTION OUTPUT ;
    USE SIGNAL ;
    PORT
      LAYER M3 ;
        RECT 89.0640 0.0000 89.0820 0.0380 ;
    END
  END p_kk[10]
  PIN p_kk[11]
    DIRECTION OUTPUT ;
    USE SIGNAL ;
    PORT
      LAYER M5 ;
        RECT 87.5520 0.0000 87.5760 0.0840 ;
    END
  END p_kk[11]
  PIN p_kk[12]
    DIRECTION OUTPUT ;
    USE SIGNAL ;
    PORT
      LAYER M3 ;
        RECT 85.9680 0.0000 85.9860 0.0380 ;
    END
  END p_kk[12]
  PIN p_kk[13]
    DIRECTION OUTPUT ;
    USE SIGNAL ;
    PORT
      LAYER M5 ;
        RECT 84.3840 0.0000 84.4080 0.0840 ;
    END
  END p_kk[13]
  PIN p_kk[14]
    DIRECTION OUTPUT ;
    USE SIGNAL ;
    PORT
      LAYER M3 ;
        RECT 82.8720 0.0000 82.8900 0.0380 ;
    END
  END p_kk[14]
  PIN p_kk[15]
    DIRECTION OUTPUT ;
    USE SIGNAL ;
    PORT
      LAYER M5 ;
        RECT 81.3120 0.0000 81.3360 0.0840 ;
    END
  END p_kk[15]
  PIN p_kk[16]
    DIRECTION OUTPUT ;
    USE SIGNAL ;
    PORT
      LAYER M3 ;
        RECT 79.7040 0.0000 79.7220 0.0380 ;
    END
  END p_kk[16]
  PIN p_kk[17]
    DIRECTION OUTPUT ;
    USE SIGNAL ;
    PORT
      LAYER M5 ;
        RECT 78.1440 0.0000 78.1680 0.0840 ;
    END
  END p_kk[17]
  PIN p_kk[18]
    DIRECTION OUTPUT ;
    USE SIGNAL ;
    PORT
      LAYER M3 ;
        RECT 76.6080 0.0000 76.6260 0.0380 ;
    END
  END p_kk[18]
  PIN p_kk[19]
    DIRECTION OUTPUT ;
    USE SIGNAL ;
    PORT
      LAYER M5 ;
        RECT 75.0720 0.0000 75.0960 0.0840 ;
    END
  END p_kk[19]
  PIN p_kk[1]
    DIRECTION OUTPUT ;
    USE SIGNAL ;
    PORT
      LAYER M5 ;
        RECT 103.1040 0.0000 103.1280 0.0840 ;
    END
  END p_kk[1]
  PIN p_kk[20]
    DIRECTION OUTPUT ;
    USE SIGNAL ;
    PORT
      LAYER M3 ;
        RECT 73.5120 0.0000 73.5300 0.0380 ;
    END
  END p_kk[20]
  PIN p_kk[21]
    DIRECTION OUTPUT ;
    USE SIGNAL ;
    PORT
      LAYER M5 ;
        RECT 72.0000 0.0000 72.0240 0.0840 ;
    END
  END p_kk[21]
  PIN p_kk[22]
    DIRECTION OUTPUT ;
    USE SIGNAL ;
    PORT
      LAYER M3 ;
        RECT 70.4160 0.0000 70.4340 0.0380 ;
    END
  END p_kk[22]
  PIN p_kk[23]
    DIRECTION OUTPUT ;
    USE SIGNAL ;
    PORT
      LAYER M5 ;
        RECT 68.8320 0.0000 68.8560 0.0840 ;
    END
  END p_kk[23]
  PIN p_kk[24]
    DIRECTION OUTPUT ;
    USE SIGNAL ;
    PORT
      LAYER M3 ;
        RECT 67.3200 0.0000 67.3380 0.0380 ;
    END
  END p_kk[24]
  PIN p_kk[25]
    DIRECTION OUTPUT ;
    USE SIGNAL ;
    PORT
      LAYER M5 ;
        RECT 65.7600 0.0000 65.7840 0.0840 ;
    END
  END p_kk[25]
  PIN p_kk[26]
    DIRECTION OUTPUT ;
    USE SIGNAL ;
    PORT
      LAYER M3 ;
        RECT 64.1520 0.0000 64.1700 0.0380 ;
    END
  END p_kk[26]
  PIN p_kk[27]
    DIRECTION OUTPUT ;
    USE SIGNAL ;
    PORT
      LAYER M5 ;
        RECT 62.5920 0.0000 62.6160 0.0840 ;
    END
  END p_kk[27]
  PIN p_kk[28]
    DIRECTION OUTPUT ;
    USE SIGNAL ;
    PORT
      LAYER M3 ;
        RECT 61.0560 0.0000 61.0740 0.0380 ;
    END
  END p_kk[28]
  PIN p_kk[29]
    DIRECTION OUTPUT ;
    USE SIGNAL ;
    PORT
      LAYER M5 ;
        RECT 59.5200 0.0000 59.5440 0.0840 ;
    END
  END p_kk[29]
  PIN p_kk[2]
    DIRECTION OUTPUT ;
    USE SIGNAL ;
    PORT
      LAYER M3 ;
        RECT 101.5200 0.0000 101.5380 0.0380 ;
    END
  END p_kk[2]
  PIN p_kk[30]
    DIRECTION OUTPUT ;
    USE SIGNAL ;
    PORT
      LAYER M3 ;
        RECT 57.9600 0.0000 57.9780 0.0380 ;
    END
  END p_kk[30]
  PIN p_kk[31]
    DIRECTION OUTPUT ;
    USE SIGNAL ;
    PORT
      LAYER M5 ;
        RECT 56.4480 0.0000 56.4720 0.0840 ;
    END
  END p_kk[31]
  PIN p_kk[3]
    DIRECTION OUTPUT ;
    USE SIGNAL ;
    PORT
      LAYER M5 ;
        RECT 99.9360 0.0000 99.9600 0.0840 ;
    END
  END p_kk[3]
  PIN p_kk[4]
    DIRECTION OUTPUT ;
    USE SIGNAL ;
    PORT
      LAYER M3 ;
        RECT 98.4240 0.0000 98.4420 0.0380 ;
    END
  END p_kk[4]
  PIN p_kk[5]
    DIRECTION OUTPUT ;
    USE SIGNAL ;
    PORT
      LAYER M5 ;
        RECT 96.8640 0.0000 96.8880 0.0840 ;
    END
  END p_kk[5]
  PIN p_kk[6]
    DIRECTION OUTPUT ;
    USE SIGNAL ;
    PORT
      LAYER M3 ;
        RECT 95.2560 0.0000 95.2740 0.0380 ;
    END
  END p_kk[6]
  PIN p_kk[7]
    DIRECTION OUTPUT ;
    USE SIGNAL ;
    PORT
      LAYER M5 ;
        RECT 93.6960 0.0000 93.7200 0.0840 ;
    END
  END p_kk[7]
  PIN p_kk[8]
    DIRECTION OUTPUT ;
    USE SIGNAL ;
    PORT
      LAYER M3 ;
        RECT 92.1600 0.0000 92.1780 0.0380 ;
    END
  END p_kk[8]
  PIN p_kk[9]
    DIRECTION OUTPUT ;
    USE SIGNAL ;
    PORT
      LAYER M5 ;
        RECT 90.6240 0.0000 90.6480 0.0840 ;
    END
  END p_kk[9]
  PIN p_v
    DIRECTION OUTPUT ;
    USE SIGNAL ;
    PORT
      LAYER M5 ;
        RECT 159.0720 0.0000 159.0960 0.0840 ;
    END
  END p_v
  PIN rst_n
    DIRECTION INPUT ;
    USE SIGNAL ;
    PORT
      LAYER M4 ;
        RECT 0.0000 173.1840 0.0840 173.2080 ;
    END
  END rst_n
  OBS
    LAYER M1 ;
      RECT 0.5 0.5 163.660 345.100 ;
    LAYER M2 ;
      RECT 0.5 0.5 163.660 345.100 ;
    LAYER M3 ;
      RECT 0.5 0.5 163.660 345.100 ;
    LAYER M4 ;
      RECT 0.5 0.5 163.660 345.100 ;
    LAYER M5 ;
      RECT 0.5 0.5 163.660 345.100 ;
    LAYER M6 ;
      RECT 0.5 0.5 163.660 345.100 ;
    LAYER M7 ;
      RECT 0.5 0.5 163.660 345.100 ;
  END
END ot_s81sl_ve_s
END LIBRARY
